VERSION 5.7 ;
BUSBITCHARS "[]" ;
DIVIDERCHAR "/" ;

PROPERTYDEFINITIONS
  MACRO lastSavedExtractCounter INTEGER ;
  MACRO CatenaDesignType STRING ;
  LAYER LEF58_TYPE STRING ;
  LAYER LEF58_SPACING STRING ;
  LAYER LEF58_WIDTH STRING ;
END PROPERTYDEFINITIONS

UNITS
  CAPACITANCE PICOFARADS 1 ;
  DATABASE MICRONS 1000 ;
END UNITS
MANUFACTURINGGRID 0.005 ;
LAYER OVERLAP
  TYPE OVERLAP ;
END OVERLAP

LAYER PW
  TYPE MASTERSLICE ;
  PROPERTY LEF58_TYPE "TYPE PWELL ;" ;
END PW

LAYER NW
  TYPE MASTERSLICE ;
  PROPERTY LEF58_TYPE "TYPE NWELL ;" ;
  PROPERTY LEF58_SPACING "SPACING 0.62 ;" ;
  PROPERTY LEF58_WIDTH "WIDTH 0.62 ;" ;
END NW

LAYER ACT
  TYPE MASTERSLICE ;
  PROPERTY LEF58_TYPE "TYPE DIFFUSION ;" ;
  PROPERTY LEF58_SPACING "SPACING 0.21 ;" ;
  PROPERTY LEF58_WIDTH "WIDTH 0.15 ;" ;
END ACT

LAYER NPLUS
  TYPE IMPLANT ;
  WIDTH 0.31 ;
  SPACING 0.31 ;
  AREA 0.25 ;
END NPLUS

LAYER PPLUS
  TYPE IMPLANT ;
  WIDTH 0.31 ;
  SPACING 0.31 ;
  AREA 0.25 ;
END PPLUS

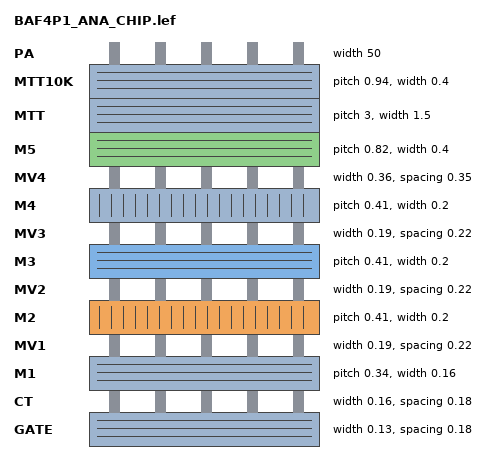
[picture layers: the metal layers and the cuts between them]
LAYER GATE
  TYPE ROUTING ;
  DIRECTION HORIZONTAL ;
  WIDTH 0.13 ;
  AREA 0.09 ;
  SPACING 0.18 ;
  MINENCLOSEDAREA 0.224 ;
  MINIMUMDENSITY 14 ;
  ANTENNAMODEL OXIDE1 ;
    ANTENNAAREARATIO 400 ;
  PROPERTY LEF58_TYPE "TYPE POLYROUTING ;" ;
END GATE

LAYER CT
  TYPE CUT ;
  SPACING 0.18 ;
  SPACING 0.2 ADJACENTCUTS 8 WITHIN 1 ;
  WIDTH 0.16 ;
  ENCLOSURE ABOVE 0 0.05 ;
  ANTENNAMODEL OXIDE1 ;
    ANTENNAAREARATIO 10 ;
END CT

LAYER M1
  TYPE ROUTING ;
  DIRECTION HORIZONTAL ;
  PITCH 0.34 0.34 ;
  WIDTH 0.16 ;
  OFFSET 0.17 0.17 ;
  AREA 0.122 ;
  SPACINGTABLE
    PARALLELRUNLENGTH 0 10.049 
    WIDTH 0 0.18 0.16 
    WIDTH 10.049 0.16 0.6 ;
  MINENCLOSEDAREA 0.2 ;
  MINIMUMDENSITY 15 ;
  MAXIMUMDENSITY 80 ;
  DENSITYCHECKWINDOW 200 200 ;
  DENSITYCHECKSTEP 100 ;
  ANTENNAMODEL OXIDE1 ;
    ANTENNAAREARATIO 600 ;
END M1

LAYER MV1
  TYPE CUT ;
  SPACING 0.22 ;
  SPACING 0.29 ADJACENTCUTS 8 WITHIN 1 ;
  WIDTH 0.19 ;
  ENCLOSURE BELOW 0.01 0.05 ;
  ENCLOSURE ABOVE 0.005 0.05 ;
  ANTENNAMODEL OXIDE1 ;
    ANTENNAAREARATIO 20 ;
END MV1

LAYER M2
  TYPE ROUTING ;
  DIRECTION VERTICAL ;
  PITCH 0.41 0.41 ;
  WIDTH 0.2 ;
  OFFSET 0.205 0.205 ;
  AREA 0.144 ;
  SPACINGTABLE
    PARALLELRUNLENGTH 0 10.049 
    WIDTH 0 0.21 0.2 
    WIDTH 10.049 0.2 0.6 ;
  MINENCLOSEDAREA 0.265 ;
  MINIMUMDENSITY 15 ;
  MAXIMUMDENSITY 80 ;
  DENSITYCHECKWINDOW 200 200 ;
  DENSITYCHECKSTEP 100 ;
  ANTENNAMODEL OXIDE1 ;
    ANTENNAAREARATIO 600 ;
END M2

LAYER MV2
  TYPE CUT ;
  SPACING 0.22 ;
  SPACING 0.29 ADJACENTCUTS 8 WITHIN 1 ;
  WIDTH 0.19 ;
  ENCLOSURE BELOW 0.005 0.05 ;
  ENCLOSURE ABOVE 0.005 0.05 ;
  ANTENNAMODEL OXIDE1 ;
    ANTENNAAREARATIO 20 ;
END MV2

LAYER M3
  TYPE ROUTING ;
  DIRECTION HORIZONTAL ;
  PITCH 0.41 0.41 ;
  WIDTH 0.2 ;
  OFFSET 0.205 0.205 ;
  AREA 0.144 ;
  SPACINGTABLE
    PARALLELRUNLENGTH 0 10.049 
    WIDTH 0 0.21 0.2 
    WIDTH 10.049 0.2 0.6 ;
  MINENCLOSEDAREA 0.265 ;
  MINIMUMDENSITY 15 ;
  MAXIMUMDENSITY 80 ;
  DENSITYCHECKWINDOW 200 200 ;
  DENSITYCHECKSTEP 100 ;
  ANTENNAMODEL OXIDE1 ;
    ANTENNAAREARATIO 600 ;
END M3

LAYER MV3
  TYPE CUT ;
  SPACING 0.22 ;
  SPACING 0.29 ADJACENTCUTS 8 WITHIN 1 ;
  WIDTH 0.19 ;
  ENCLOSURE BELOW 0.005 0.05 ;
  ENCLOSURE ABOVE 0.005 0.05 ;
  ANTENNAMODEL OXIDE1 ;
    ANTENNAAREARATIO 20 ;
END MV3

LAYER M4
  TYPE ROUTING ;
  DIRECTION VERTICAL ;
  PITCH 0.41 0.41 ;
  WIDTH 0.2 ;
  OFFSET 0.205 0.205 ;
  AREA 0.144 ;
  SPACINGTABLE
    PARALLELRUNLENGTH 0 10.049 
    WIDTH 0 0.21 0.2 
    WIDTH 10.049 0.2 0.6 ;
  MINENCLOSEDAREA 0.265 ;
  MINIMUMDENSITY 15 ;
  MAXIMUMDENSITY 80 ;
  DENSITYCHECKWINDOW 200 200 ;
  DENSITYCHECKSTEP 100 ;
  ANTENNAMODEL OXIDE1 ;
    ANTENNAAREARATIO 600 ;
END M4

LAYER MV4
  TYPE CUT ;
  SPACING 0.35 ;
  SPACING 0.54 ADJACENTCUTS 8 WITHIN 1 ;
  WIDTH 0.36 ;
  ENCLOSURE BELOW 0.01 0.05 ;
  ENCLOSURE ABOVE 0.02 0.02 ;
  ANTENNAMODEL OXIDE1 ;
    ANTENNAAREARATIO 20 ;
END MV4

LAYER M5
  TYPE ROUTING ;
  DIRECTION HORIZONTAL ;
  PITCH 0.82 0.82 ;
  WIDTH 0.4 ;
  OFFSET 0.41 0.41 ;
  AREA 0.562 ;
  SPACINGTABLE
    PARALLELRUNLENGTH 0 10.049 
    WIDTH 0 0.42 0.4 
    WIDTH 10.049 0.4 0.6 ;
  MINENCLOSEDAREA 0.565 ;
  MINIMUMDENSITY 20 ;
  MAXIMUMDENSITY 80 ;
  DENSITYCHECKWINDOW 200 200 ;
  DENSITYCHECKSTEP 100 ;
  ANTENNAMODEL OXIDE1 ;
    ANTENNAAREARATIO 600 ;
END M5

LAYER MTT
  TYPE ROUTING ;
  DIRECTION HORIZONTAL ;
  PITCH 3 3 ;
  WIDTH 1.5 ;
  OFFSET 1.5 1.5 ;
  AREA 2.25 ;
  SPACINGTABLE
    PARALLELRUNLENGTH 0 16.049 
    WIDTH 0 1.5 1.5 
    WIDTH 16.049 1.5 3 ;
  MINIMUMDENSITY 30 ;
  DENSITYCHECKWINDOW 200 200 ;
  DENSITYCHECKSTEP 100 ;
  ANTENNAMODEL OXIDE1 ;
    ANTENNAAREARATIO 600 ;
END MTT

LAYER MTT10K
  TYPE ROUTING ;
  DIRECTION HORIZONTAL ;
  PITCH 0.94 0.94 ;
  WIDTH 0.4 ;
  OFFSET 0.47 0.47 ;
  AREA 0.562 ;
  SPACINGTABLE
    PARALLELRUNLENGTH 0 10.049 
    WIDTH 0 0.54 0.4 
    WIDTH 10.049 0.4 0.6 ;
  MINENCLOSEDAREA 0.565 ;
  MINIMUMDENSITY 20 ;
  MAXIMUMDENSITY 80 ;
  DENSITYCHECKWINDOW 200 200 ;
  DENSITYCHECKSTEP 100 ;
  ANTENNAMODEL OXIDE1 ;
    ANTENNAAREARATIO 600 ;
END MTT10K

LAYER PA
  TYPE CUT ;
  PROPERTY LEF58_TYPE "TYPE PASSIVATION ;" ;
  WIDTH 50 ;
  ENCLOSURE BELOW 2 2 ;
END PA

VIARULE PGR GENERATE DEFAULT
  LAYER ACT ;
    ENCLOSURE 0.07 0.07 ;
  LAYER M1 ;
    ENCLOSURE 0.05 0.05 ;
  LAYER CT ;
    RECT -0.08 -0.08 0.08 0.08 ;
    SPACING 0.34 BY 0.34 ;
END PGR

VIARULE REC_PGR GENERATE DEFAULT
  LAYER ACT ;
    ENCLOSURE 0.12 0.12 ;
  LAYER M1 ;
    ENCLOSURE 0.08 0.08 ;
  LAYER CT ;
    RECT -0.08 -0.08 0.08 0.08 ;
    SPACING 0.34 BY 0.34 ;
END REC_PGR

VIARULE NGR GENERATE DEFAULT
  LAYER ACT ;
    ENCLOSURE 0.07 0.07 ;
  LAYER M1 ;
    ENCLOSURE 0.05 0.05 ;
  LAYER CT ;
    RECT -0.08 -0.08 0.08 0.08 ;
    SPACING 0.34 BY 0.34 ;
END NGR

VIARULE REC_NGR GENERATE DEFAULT
  LAYER ACT ;
    ENCLOSURE 0.12 0.12 ;
  LAYER M1 ;
    ENCLOSURE 0.08 0.08 ;
  LAYER CT ;
    RECT -0.08 -0.08 0.08 0.08 ;
    SPACING 0.34 BY 0.34 ;
END REC_NGR

VIARULE M1_ACT GENERATE DEFAULT
  LAYER ACT ;
    ENCLOSURE 0.07 0.07 ;
  LAYER M1 ;
    ENCLOSURE 0.05 0 ;
  LAYER CT ;
    RECT -0.08 -0.08 0.08 0.08 ;
    SPACING 0.34 BY 0.34 ;
END M1_ACT

VIARULE REC_M1_ACT GENERATE DEFAULT
  LAYER ACT ;
    ENCLOSURE 0.12 0.12 ;
  LAYER M1 ;
    ENCLOSURE 0.08 0.08 ;
  LAYER CT ;
    RECT -0.08 -0.08 0.08 0.08 ;
    SPACING 0.34 BY 0.34 ;
END REC_M1_ACT

VIARULE M1_GATE GENERATE DEFAULT
  LAYER GATE ;
    ENCLOSURE 0.07 0.07 ;
  LAYER M1 ;
    ENCLOSURE 0.05 0 ;
  LAYER CT ;
    RECT -0.08 -0.08 0.08 0.08 ;
    SPACING 0.34 BY 0.34 ;
END M1_GATE

VIARULE REC_M1_GATE GENERATE DEFAULT
  LAYER GATE ;
    ENCLOSURE 0.12 0.12 ;
  LAYER M1 ;
    ENCLOSURE 0.08 0.08 ;
  LAYER CT ;
    RECT -0.08 -0.08 0.08 0.08 ;
    SPACING 0.34 BY 0.34 ;
END REC_M1_GATE

VIARULE M2_M1 GENERATE DEFAULT
  LAYER M1 ;
    ENCLOSURE 0.05 0.01 ;
  LAYER M2 ;
    ENCLOSURE 0.05 0.005 ;
  LAYER MV1 ;
    RECT -0.095 -0.095 0.095 0.095 ;
    SPACING 0.41 BY 0.41 ;
END M2_M1

VIARULE REC_M2_M1 GENERATE DEFAULT
  LAYER M1 ;
    ENCLOSURE 0.08 0.05 ;
  LAYER M2 ;
    ENCLOSURE 0.05 0.05 ;
  LAYER MV1 ;
    RECT -0.095 -0.095 0.095 0.095 ;
    SPACING 0.41 BY 0.41 ;
END REC_M2_M1

VIARULE M3_M2 GENERATE DEFAULT
  LAYER M2 ;
    ENCLOSURE 0.05 0.005 ;
  LAYER M3 ;
    ENCLOSURE 0.05 0.005 ;
  LAYER MV2 ;
    RECT -0.095 -0.095 0.095 0.095 ;
    SPACING 0.41 BY 0.41 ;
END M3_M2

VIARULE REC_M3_M2 GENERATE DEFAULT
  LAYER M2 ;
    ENCLOSURE 0.08 0.05 ;
  LAYER M3 ;
    ENCLOSURE 0.05 0.05 ;
  LAYER MV2 ;
    RECT -0.095 -0.095 0.095 0.095 ;
    SPACING 0.41 BY 0.41 ;
END REC_M3_M2

VIARULE M4_M3 GENERATE DEFAULT
  LAYER M3 ;
    ENCLOSURE 0.05 0.005 ;
  LAYER M4 ;
    ENCLOSURE 0.05 0.005 ;
  LAYER MV3 ;
    RECT -0.095 -0.095 0.095 0.095 ;
    SPACING 0.41 BY 0.41 ;
END M4_M3

VIARULE REC_M4_M3 GENERATE DEFAULT
  LAYER M3 ;
    ENCLOSURE 0.08 0.05 ;
  LAYER M4 ;
    ENCLOSURE 0.05 0.05 ;
  LAYER MV3 ;
    RECT -0.095 -0.095 0.095 0.095 ;
    SPACING 0.41 BY 0.41 ;
END REC_M4_M3

VIARULE M5_M4 GENERATE DEFAULT
  LAYER M4 ;
    ENCLOSURE 0.05 0.01 ;
  LAYER M5 ;
    ENCLOSURE 0.11 0.02 ;
  LAYER MV4 ;
    RECT -0.18 -0.18 0.18 0.18 ;
    SPACING 0.71 BY 0.71 ;
END M5_M4

VIARULE M5_M4_SQUARE GENERATE DEFAULT
  LAYER M4 ;
    ENCLOSURE 0.05 0.01 ;
  LAYER M5 ;
    ENCLOSURE 0.09 0.09 ;
  LAYER MV4 ;
    RECT -0.18 -0.18 0.18 0.18 ;
    SPACING 0.71 BY 0.71 ;
END M5_M4_SQUARE

VIARULE MTT_M4 GENERATE DEFAULT
  LAYER M4 ;
    ENCLOSURE 0.05 0.01 ;
  LAYER MTT ;
    ENCLOSURE 0.45 0.3 ;
  LAYER MV4 ;
    RECT -0.18 -0.18 0.18 0.18 ;
    SPACING 0.71 BY 0.71 ;
END MTT_M4

VIARULE MTT10K_M4 GENERATE DEFAULT
  LAYER M4 ;
    ENCLOSURE 0.05 0.01 ;
  LAYER MTT10K ;
    ENCLOSURE 0.11 0.02 ;
  LAYER MV4 ;
    RECT -0.18 -0.18 0.18 0.18 ;
    SPACING 0.71 BY 0.71 ;
END MTT10K_M4

VIARULE MTT10K_M4_SQUARE GENERATE DEFAULT
  LAYER M4 ;
    ENCLOSURE 0.05 0.01 ;
  LAYER MTT10K ;
    ENCLOSURE 0.09 0.09 ;
  LAYER MV4 ;
    RECT -0.18 -0.18 0.18 0.18 ;
    SPACING 0.71 BY 0.71 ;
END MTT10K_M4_SQUARE

VIA M2_M1_0
  VIARULE M2_M1 ;
  CUTSIZE 0.19 0.19 ;
  LAYERS M1 MV1 M2 ;
  CUTSPACING 0.22 0.22 ;
  ENCLOSURE 0.05 0.01 0.05 0.005 ;
  ROWCOL 1 1 ;
END M2_M1_0

VIA M2_M1_1
  VIARULE M2_M1 ;
  CUTSIZE 0.19 0.19 ;
  LAYERS M1 MV1 M2 ;
  CUTSPACING 0.29 0.29 ;
  ENCLOSURE 0.065 0.245 0.065 0.245 ;
  ROWCOL 10 42 ;
END M2_M1_1

VIA M4_M3_2
  VIARULE M4_M3 ;
  CUTSIZE 0.19 0.19 ;
  LAYERS M3 MV3 M4 ;
  CUTSPACING 0.29 0.29 ;
  ENCLOSURE 0.065 0.005 0.065 0.005 ;
  ROWCOL 11 42 ;
END M4_M3_2

VIA M5_M4_3
  VIARULE M5_M4 ;
  CUTSIZE 0.36 0.36 ;
  LAYERS M4 MV4 M5 ;
  CUTSPACING 0.35 0.35 ;
  ENCLOSURE 0.05 0.01 0.11 0.02 ;
  ROWCOL 1 1 ;
END M5_M4_3

VIA M4_M3_4
  VIARULE M4_M3 ;
  CUTSIZE 0.19 0.19 ;
  LAYERS M3 MV3 M4 ;
  CUTSPACING 0.22 0.29 ;
  ENCLOSURE 0.15 0.165 0.15 0.165 ;
  ROWCOL 2 12 ;
END M4_M3_4

VIA M4_M3_5
  VIARULE M4_M3 ;
  CUTSIZE 0.19 0.19 ;
  LAYERS M3 MV3 M4 ;
  CUTSPACING 0.22 0.22 ;
  ENCLOSURE 0.05 0.005 0.05 0.005 ;
  ROWCOL 1 1 ;
END M4_M3_5

VIA M2_M1_6
  VIARULE M2_M1 ;
  CUTSIZE 0.19 0.19 ;
  LAYERS M1 MV1 M2 ;
  CUTSPACING 0.29 0.29 ;
  ENCLOSURE 0.01 0.245 0.005 0.245 ;
  ROWCOL 10 11 ;
END M2_M1_6

VIA M5_M4_7
  VIARULE M5_M4 ;
  CUTSIZE 0.36 0.36 ;
  LAYERS M4 MV4 M5 ;
  CUTSPACING 0.54 0.54 ;
  ENCLOSURE 0.37 0.07 0.37 0.07 ;
  ROWCOL 6 22 ;
END M5_M4_7

VIA M5_M4_8
  VIARULE M5_M4 ;
  CUTSIZE 0.36 0.36 ;
  LAYERS M4 MV4 M5 ;
  CUTSPACING 0.35 0.35 ;
  ENCLOSURE 0.19 0.32 0.19 0.32 ;
  ROWCOL 1 7 ;
END M5_M4_8

VIA M3_M2_9
  VIARULE M3_M2 ;
  CUTSIZE 0.19 0.19 ;
  LAYERS M2 MV2 M3 ;
  CUTSPACING 0.22 0.22 ;
  ENCLOSURE 0.05 0.005 0.05 0.005 ;
  ROWCOL 1 1 ;
END M3_M2_9

VIA M2_M1_10
  VIARULE M2_M1 ;
  CUTSIZE 0.19 0.19 ;
  LAYERS M1 MV1 M2 ;
  CUTSPACING 0.29 0.22 ;
  ENCLOSURE 0.165 0.15 0.165 0.15 ;
  ROWCOL 12 2 ;
END M2_M1_10

VIA M3_M2_11
  VIARULE M3_M2 ;
  CUTSIZE 0.19 0.19 ;
  LAYERS M2 MV2 M3 ;
  CUTSPACING 0.29 0.22 ;
  ENCLOSURE 0.165 0.055 0.165 0.055 ;
  ROWCOL 1 2 ;
END M3_M2_11

VIA M3_M2_12
  VIARULE M3_M2 ;
  CUTSIZE 0.19 0.19 ;
  LAYERS M2 MV2 M3 ;
  CUTSPACING 0.29 0.22 ;
  ENCLOSURE 0.165 0.055 0.165 0.055 ;
  ROWCOL 2 2 ;
END M3_M2_12

VIA M3_M2_13
  VIARULE M3_M2 ;
  CUTSIZE 0.19 0.19 ;
  LAYERS M2 MV2 M3 ;
  CUTSPACING 0.29 0.29 ;
  ENCLOSURE 0.065 0.005 0.065 0.005 ;
  ROWCOL 11 42 ;
END M3_M2_13

VIA M3_M2_14
  VIARULE M3_M2 ;
  CUTSIZE 0.19 0.19 ;
  LAYERS M2 MV2 M3 ;
  CUTSPACING 0.29 0.22 ;
  ENCLOSURE 0.165 0.055 0.165 0.055 ;
  ROWCOL 12 2 ;
END M3_M2_14

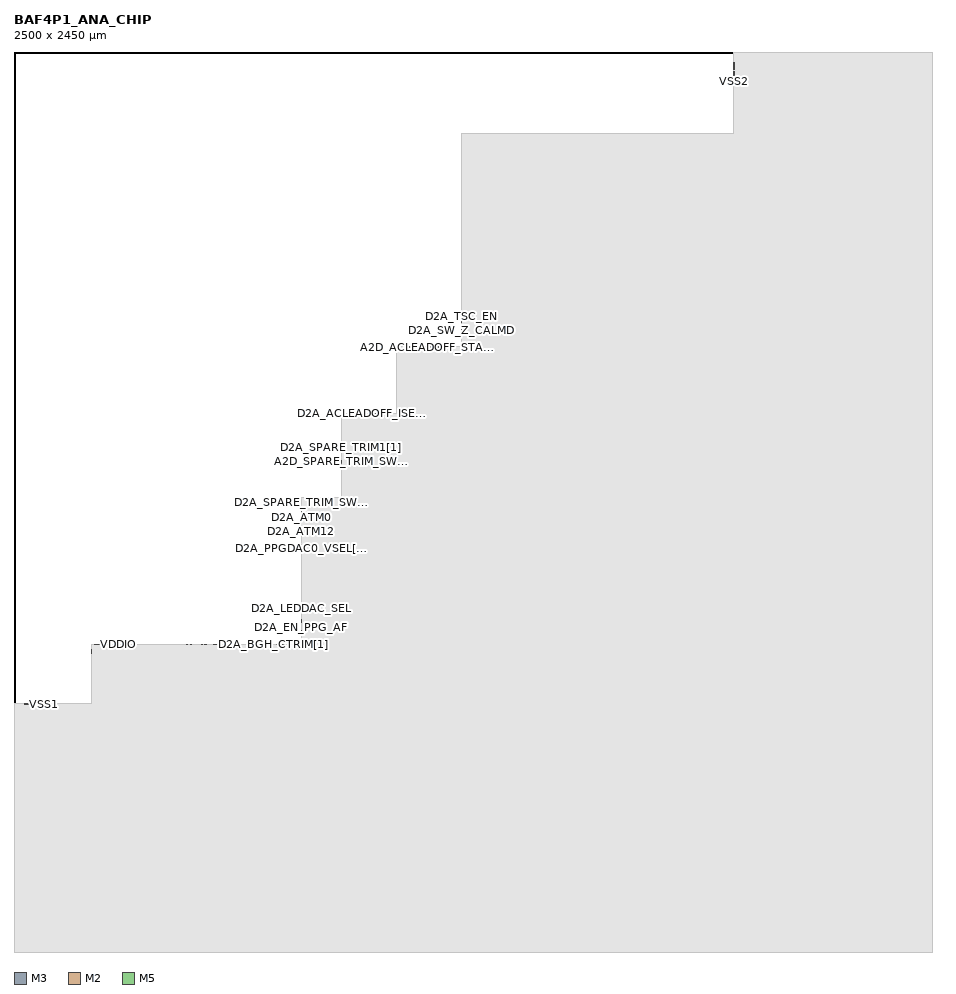
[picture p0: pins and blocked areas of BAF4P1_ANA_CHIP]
MACRO BAF4P1_ANA_CHIP
  CLASS BLOCK ;
  ORIGIN 0 0 ;
  FOREIGN BAF4P1_ANA_CHIP 0 0 ;
  SIZE 2500 BY 2450 ;
  PIN D2A_ECG_DDA_ISEL[0]
    DIRECTION INPUT ;
    USE SIGNAL ;
    PORT
      LAYER M3 ;
        RECT 1154.455 1646.7 1154.755 1647 ;
    END
  END D2A_ECG_DDA_ISEL[0]
  PIN D2A_ECG_DDA_GSEL[1]
    DIRECTION INPUT ;
    USE SIGNAL ;
    PORT
      LAYER M3 ;
        RECT 1145.355 1646.7 1145.655 1647 ;
    END
  END D2A_ECG_DDA_GSEL[1]
  PIN D2A_EN_PPG_BUFFER
    DIRECTION INPUT ;
    USE SIGNAL ;
    PORT
      LAYER M3 ;
        RECT 782 878.81 782.2 879.11 ;
    END
  END D2A_EN_PPG_BUFFER
  PIN D2A_LED_EN
    DIRECTION INPUT ;
    USE SIGNAL ;
    PORT
      LAYER M3 ;
        RECT 782 908.71 782.2 909.01 ;
    END
  END D2A_LED_EN
  PIN D2A_PPG_TEST_IN[0]
    DIRECTION INPUT ;
    USE SIGNAL ;
    PORT
      LAYER M3 ;
        RECT 782 885.31 782.2 885.61 ;
    END
  END D2A_PPG_TEST_IN[0]
  PIN A2D_SPARE_TRIM_SW0[1]
    DIRECTION OUTPUT ;
    USE SIGNAL ;
    PORT
      LAYER M3 ;
        RECT 891.37 1336.39 891.67 1337.39 ;
    END
  END A2D_SPARE_TRIM_SW0[1]
  PIN D2A_EN_PPG_AF
    DIRECTION INPUT ;
    USE SIGNAL ;
    PORT
      LAYER M3 ;
        RECT 782 882.71 782.2 883.01 ;
    END
  END D2A_EN_PPG_AF
  PIN D2A_LED_STANDBYEN
    DIRECTION INPUT ;
    USE SIGNAL ;
    PORT
      LAYER M3 ;
        RECT 782 907.41 782.2 907.71 ;
    END
  END D2A_LED_STANDBYEN
  PIN D2A_SPARE_TRIM_SW0[1]
    DIRECTION INPUT ;
    USE SIGNAL ;
    PORT
      LAYER M3 ;
        RECT 782 1193.84 782.3 1194.14 ;
    END
  END D2A_SPARE_TRIM_SW0[1]
  PIN D2A_TSC_INA_EN
    DIRECTION INPUT ;
    USE SIGNAL ;
    PORT
      LAYER M3 ;
        RECT 1217.84 1719.36 1218.14 1719.66 ;
    END
  END D2A_TSC_INA_EN
  PIN VSS_DIG_AO
    DIRECTION INOUT ;
    USE SIGNAL ;
    PORT
      LAYER M2 ;
        RECT 721.265 835.925 722.265 836.225 ;
    END
    PORT
      LAYER M2 ;
        RECT 691.245 835.925 692.245 836.225 ;
    END
    PORT
      LAYER M2 ;
        RECT 556.465 835.925 557.465 836.225 ;
    END
    PORT
      LAYER M2 ;
        RECT 468.87 835.925 469.87 836.225 ;
    END
    PORT
      LAYER M3 ;
        RECT 509.465 835.925 514.465 836.225 ;
    END
    PORT
      LAYER M2 ;
        RECT 782 1157.215 782.3 1158.215 ;
    END
    PORT
      LAYER M2 ;
        RECT 782 871.21 782.2 872.21 ;
    END
    PORT
      LAYER M2 ;
        RECT 782 920.31 782.3 921.31 ;
    END
    PORT
      LAYER M2 ;
        RECT 782 1189.54 782.3 1190.54 ;
    END
    PORT
      LAYER M2 ;
        RECT 1217.84 1667.005 1218.14 1668.005 ;
    END
    PORT
      LAYER M2 ;
        RECT 891.37 1328.895 891.67 1329.895 ;
    END
    PORT
      LAYER M2 ;
        RECT 891.37 1356.66 891.67 1357.66 ;
    END
    PORT
      LAYER M2 ;
        RECT 891.37 1382.375 891.67 1383.375 ;
    END
    PORT
      LAYER M2 ;
        RECT 1164.555 1646.7 1165.555 1647 ;
    END
    PORT
      LAYER M2 ;
        RECT 782 1099.485 782.2 1100.485 ;
    END
    PORT
      LAYER M2 ;
        RECT 1217.84 1714.655 1218.14 1715.655 ;
    END
    PORT
      LAYER M2 ;
        RECT 981.735 1464.88 982.735 1465.18 ;
    END
    PORT
      LAYER M2 ;
        RECT 923.735 1464.88 924.735 1465.18 ;
    END
    PORT
      LAYER M2 ;
        RECT 782 1138.835 782.3 1139.835 ;
    END
    PORT
      LAYER M2 ;
        RECT 1068.26 1646.7 1069.26 1647 ;
    END
  END VSS_DIG_AO
  PIN D2A_ACLEADOFF_VTHPSEL_TRIM[2]
    DIRECTION INPUT ;
    USE SIGNAL ;
    PORT
      LAYER M3 ;
        RECT 1112.755 1646.7 1113.055 1647 ;
    END
  END D2A_ACLEADOFF_VTHPSEL_TRIM[2]
  PIN D2A_DCLEADOFF_ISEL_TRIM[6]
    DIRECTION INPUT ;
    USE SIGNAL ;
    PORT
      LAYER M3 ;
        RECT 957.335 1464.88 957.635 1465.18 ;
    END
  END D2A_DCLEADOFF_ISEL_TRIM[6]
  PIN D2A_DCLEADOFF_ISEL_TRIM[7]
    DIRECTION INPUT ;
    USE SIGNAL ;
    PORT
      LAYER M3 ;
        RECT 956.035 1464.88 956.335 1465.18 ;
    END
  END D2A_DCLEADOFF_ISEL_TRIM[7]
  PIN D2A_TIA_GAIN[0]
    DIRECTION INPUT ;
    USE SIGNAL ;
    PORT
      LAYER M3 ;
        RECT 782 906.11 782.2 906.41 ;
    END
  END D2A_TIA_GAIN[0]
  PIN A2D_external_clock_I
    DIRECTION OUTPUT ;
    USE SIGNAL ;
    PORT
      LAYER M3 ;
        RECT 522.465 835.925 523.465 836.225 ;
    END
  END A2D_external_clock_I
  PIN D2A_EN_PPGDAC_BUFFER
    DIRECTION INPUT ;
    USE SIGNAL ;
    PORT
      LAYER M3 ;
        RECT 782 913.91 782.2 914.21 ;
    END
  END D2A_EN_PPGDAC_BUFFER
  PIN D2A_ECG_PGA_GSEL[1]
    DIRECTION INPUT ;
    USE SIGNAL ;
    PORT
      LAYER M3 ;
        RECT 1160.955 1646.7 1161.255 1647 ;
    END
  END D2A_ECG_PGA_GSEL[1]
  PIN D2A_ACLEADOFF_VTHPSEL_TRIM[1]
    DIRECTION INPUT ;
    USE SIGNAL ;
    PORT
      LAYER M3 ;
        RECT 1111.455 1646.7 1111.755 1647 ;
    END
  END D2A_ACLEADOFF_VTHPSEL_TRIM[1]
  PIN D2A_DCLEADOFF_COMP_TH_TRIM[7]
    DIRECTION INPUT ;
    USE SIGNAL ;
    PORT
      LAYER M3 ;
        RECT 949.535 1464.88 949.835 1465.18 ;
    END
  END D2A_DCLEADOFF_COMP_TH_TRIM[7]
  PIN D2A_ECGCAL_EN
    DIRECTION INPUT ;
    USE SIGNAL ;
    PORT
      LAYER M3 ;
        RECT 1141.755 1646.7 1142.055 1647 ;
    END
  END D2A_ECGCAL_EN
  PIN D2A_TIA_IDAC[6]
    DIRECTION INPUT ;
    USE SIGNAL ;
    PORT
      LAYER M3 ;
        RECT 782 887.91 782.2 888.21 ;
    END
  END D2A_TIA_IDAC[6]
  PIN D2A_DCLEADOFF_COMP_TH_TRIM[6]
    DIRECTION INPUT ;
    USE SIGNAL ;
    PORT
      LAYER M3 ;
        RECT 950.835 1464.88 951.135 1465.18 ;
    END
  END D2A_DCLEADOFF_COMP_TH_TRIM[6]
  PIN D2A_DCLEADOFF_COMP_TH_TRIM[3]
    DIRECTION INPUT ;
    USE SIGNAL ;
    PORT
      LAYER M3 ;
        RECT 954.735 1464.88 955.035 1465.18 ;
    END
  END D2A_DCLEADOFF_COMP_TH_TRIM[3]
  PIN D2A_PPGDAC0_VSEL[1]
    DIRECTION INPUT ;
    USE SIGNAL ;
    PORT
      LAYER M3 ;
        RECT 782 1120.685 782.3 1120.985 ;
    END
  END D2A_PPGDAC0_VSEL[1]
  PIN D2A_SPARE_TRIM0[6]
    DIRECTION INPUT ;
    USE SIGNAL ;
    PORT
      LAYER M3 ;
        RECT 978.135 1464.88 978.435 1465.18 ;
    END
  END D2A_SPARE_TRIM0[6]
  PIN D2A_SW_Z_DDS[3]
    DIRECTION INPUT ;
    USE SIGNAL ;
    PORT
      LAYER M3 ;
        RECT 1217.84 1685.68 1218.14 1685.98 ;
    END
  END D2A_SW_Z_DDS[3]
  PIN D2A_PPGDAC1_VSEL[9]
    DIRECTION INPUT ;
    USE SIGNAL ;
    PORT
      LAYER M3 ;
        RECT 782 1114.185 782.3 1114.485 ;
    END
  END D2A_PPGDAC1_VSEL[9]
  PIN D2A_DCLEADOFF_COMP_TH_TRIM[4]
    DIRECTION INPUT ;
    USE SIGNAL ;
    PORT
      LAYER M3 ;
        RECT 953.435 1464.88 953.735 1465.18 ;
    END
  END D2A_DCLEADOFF_COMP_TH_TRIM[4]
  PIN D2A_ATM3
    DIRECTION INPUT ;
    USE SIGNAL ;
    PORT
      LAYER M3 ;
        RECT 782 1178.74 782.3 1179.04 ;
    END
  END D2A_ATM3
  PIN D2A_ECGCAL_VSEL_TRIM[2]
    DIRECTION INPUT ;
    USE SIGNAL ;
    PORT
      LAYER M3 ;
        RECT 1131.355 1646.7 1131.655 1647 ;
    END
  END D2A_ECGCAL_VSEL_TRIM[2]
  PIN D2A_ACLEADOFF_ISEL_TRIM[1]
    DIRECTION INPUT ;
    USE SIGNAL ;
    PORT
      LAYER M3 ;
        RECT 1119.255 1646.7 1119.555 1647 ;
    END
  END D2A_ACLEADOFF_ISEL_TRIM[1]
  PIN D2A_TSC_EN
    DIRECTION INPUT ;
    USE SIGNAL ;
    PORT
      LAYER M3 ;
        RECT 1217.84 1708.405 1218.14 1708.705 ;
    END
  END D2A_TSC_EN
  PIN D2A_SPARE_TRIM2[1]
    DIRECTION INPUT ;
    USE SIGNAL ;
    PORT
      LAYER M3 ;
        RECT 891.37 1361.885 891.67 1362.185 ;
    END
  END D2A_SPARE_TRIM2[1]
  PIN D2A_OSC_ISEL_TRIM[1]
    DIRECTION INPUT ;
    USE SIGNAL ;
    PORT
      LAYER M3 ;
        RECT 734.765 835.925 735.065 836.225 ;
    END
  END D2A_OSC_ISEL_TRIM[1]
  PIN D2A_SPARE_TRIM2[6]
    DIRECTION INPUT ;
    USE SIGNAL ;
    PORT
      LAYER M3 ;
        RECT 891.37 1368.385 891.67 1368.685 ;
    END
  END D2A_SPARE_TRIM2[6]
  PIN D2A_LDO1V5_VTRIM[4]
    DIRECTION INPUT ;
    USE SIGNAL ;
    PORT
      LAYER M3 ;
        RECT 479.17 835.925 479.47 836.225 ;
    END
  END D2A_LDO1V5_VTRIM[4]
  PIN D2A_ACLEADOFF_ISEL_TRIM[7]
    DIRECTION INPUT ;
    USE SIGNAL ;
    PORT
      LAYER M3 ;
        RECT 941.735 1464.88 942.035 1465.18 ;
    END
  END D2A_ACLEADOFF_ISEL_TRIM[7]
  PIN A2D_SPARE_TRIM_SW0[2]
    DIRECTION OUTPUT ;
    USE SIGNAL ;
    PORT
      LAYER M3 ;
        RECT 891.37 1339.39 891.67 1340.39 ;
    END
  END A2D_SPARE_TRIM_SW0[2]
  PIN D2A_SDM_BIAS[0]
    DIRECTION INPUT ;
    USE SIGNAL ;
    PORT
      LAYER M3 ;
        RECT 1077.855 1646.7 1078.155 1647 ;
    END
  END D2A_SDM_BIAS[0]
  PIN D2A_BIST_EN
    DIRECTION INPUT ;
    USE SIGNAL ;
    PORT
      LAYER M3 ;
        RECT 782 1160.54 782.3 1160.84 ;
    END
  END D2A_BIST_EN
  PIN D2A_PPGDAC0_VSEL[6]
    DIRECTION INPUT ;
    USE SIGNAL ;
    PORT
      LAYER M3 ;
        RECT 782 1127.185 782.3 1127.485 ;
    END
  END D2A_PPGDAC0_VSEL[6]
  PIN D2A_BGH_CTRIM[0]
    DIRECTION INPUT ;
    USE SIGNAL ;
    PORT
      LAYER M3 ;
        RECT 705.915 835.925 706.215 836.225 ;
    END
  END D2A_BGH_CTRIM[0]
  PIN D2A_BIST_ISEL[1]
    DIRECTION INPUT ;
    USE SIGNAL ;
    PORT
      LAYER M3 ;
        RECT 782 1163.14 782.3 1163.44 ;
    END
  END D2A_BIST_ISEL[1]
  PIN D2A_VCM1P5_BUF_EN
    DIRECTION INPUT ;
    USE SIGNAL ;
    PORT
      LAYER M3 ;
        RECT 782 1183.94 782.3 1184.24 ;
    END
  END D2A_VCM1P5_BUF_EN
  PIN D2A_SPARE_TRIM1[7]
    DIRECTION INPUT ;
    USE SIGNAL ;
    PORT
      LAYER M3 ;
        RECT 891.37 1380.085 891.67 1380.385 ;
    END
  END D2A_SPARE_TRIM1[7]
  PIN D2A_ATM6
    DIRECTION INPUT ;
    USE SIGNAL ;
    PORT
      LAYER M3 ;
        RECT 782 1174.84 782.3 1175.14 ;
    END
  END D2A_ATM6
  PIN D2A_EN_TIA
    DIRECTION INPUT ;
    USE SIGNAL ;
    PORT
      LAYER M3 ;
        RECT 782 900.91 782.2 901.21 ;
    END
  END D2A_EN_TIA
  PIN D2A_Z_EN
    DIRECTION INPUT ;
    USE SIGNAL ;
    PORT
      LAYER M3 ;
        RECT 1217.84 1692.18 1218.14 1692.48 ;
    END
  END D2A_Z_EN
  PIN D2A_PPGDAC0_VSEL[5]
    DIRECTION INPUT ;
    USE SIGNAL ;
    PORT
      LAYER M3 ;
        RECT 782 1125.885 782.3 1126.185 ;
    END
  END D2A_PPGDAC0_VSEL[5]
  PIN D2A_SW_Z_TX_GSEL[0]
    DIRECTION INPUT ;
    USE SIGNAL ;
    PORT
      LAYER M3 ;
        RECT 1217.84 1675.305 1218.14 1675.605 ;
    END
  END D2A_SW_Z_TX_GSEL[0]
  PIN D2A_TIA_IDAC[7]
    DIRECTION INPUT ;
    USE SIGNAL ;
    PORT
      LAYER M3 ;
        RECT 782 886.61 782.2 886.91 ;
    END
  END D2A_TIA_IDAC[7]
  PIN D2A_PPG_TEST_OUT[0]
    DIRECTION INPUT ;
    USE SIGNAL ;
    PORT
      LAYER M3 ;
        RECT 782 876.21 782.2 876.51 ;
    END
  END D2A_PPG_TEST_OUT[0]
  PIN D2A_DCLEADOFF_RMODE_EN
    DIRECTION INPUT ;
    USE SIGNAL ;
    PORT
      LAYER M3 ;
        RECT 1095.15 1646.7 1095.45 1647 ;
    END
  END D2A_DCLEADOFF_RMODE_EN
  PIN D2A_TSC_OUT_SEL
    DIRECTION INPUT ;
    USE SIGNAL ;
    PORT
      LAYER M3 ;
        RECT 1217.84 1707.105 1218.14 1707.405 ;
    END
  END D2A_TSC_OUT_SEL
  PIN D2A_SPARE_TRIM0[5]
    DIRECTION INPUT ;
    USE SIGNAL ;
    PORT
      LAYER M3 ;
        RECT 976.835 1464.88 977.135 1465.18 ;
    END
  END D2A_SPARE_TRIM0[5]
  PIN D2A_SPARE_TRIM_SW1[2]
    DIRECTION INPUT ;
    USE SIGNAL ;
    PORT
      LAYER M3 ;
        RECT 686.345 835.925 686.645 836.225 ;
    END
  END D2A_SPARE_TRIM_SW1[2]
  PIN D2A_SPARE_TRIM_SW1[5]
    DIRECTION INPUT ;
    USE SIGNAL ;
    PORT
      LAYER M3 ;
        RECT 682.445 835.925 682.745 836.225 ;
    END
  END D2A_SPARE_TRIM_SW1[5]
  PIN D2A_SPARE_TRIM0[0]
    DIRECTION INPUT ;
    USE SIGNAL ;
    PORT
      LAYER M3 ;
        RECT 970.335 1464.88 970.635 1465.18 ;
    END
  END D2A_SPARE_TRIM0[0]
  PIN D2A_SPARE_TRIM_SW1[3]
    DIRECTION INPUT ;
    USE SIGNAL ;
    PORT
      LAYER M3 ;
        RECT 685.045 835.925 685.345 836.225 ;
    END
  END D2A_SPARE_TRIM_SW1[3]
  PIN D2A_SPARE_TRIM0[7]
    DIRECTION INPUT ;
    USE SIGNAL ;
    PORT
      LAYER M3 ;
        RECT 979.435 1464.88 979.735 1465.18 ;
    END
  END D2A_SPARE_TRIM0[7]
  PIN D2A_RLD_EN
    DIRECTION INPUT ;
    USE SIGNAL ;
    PORT
      LAYER M3 ;
        RECT 1086.655 1646.7 1086.955 1647 ;
    END
  END D2A_RLD_EN
  PIN D2A_SPARE_TRIM0[3]
    DIRECTION INPUT ;
    USE SIGNAL ;
    PORT
      LAYER M3 ;
        RECT 974.235 1464.88 974.535 1465.18 ;
    END
  END D2A_SPARE_TRIM0[3]
  PIN D2A_TIA_IDAC[2]
    DIRECTION INPUT ;
    USE SIGNAL ;
    PORT
      LAYER M3 ;
        RECT 782 893.11 782.2 893.41 ;
    END
  END D2A_TIA_IDAC[2]
  PIN D2A_SPARE_TRIM1[4]
    DIRECTION INPUT ;
    USE SIGNAL ;
    PORT
      LAYER M3 ;
        RECT 891.37 1376.185 891.67 1376.485 ;
    END
  END D2A_SPARE_TRIM1[4]
  PIN D2A_ECG_PGA_EN
    DIRECTION INPUT ;
    USE SIGNAL ;
    PORT
      LAYER M3 ;
        RECT 1157.055 1646.7 1157.355 1647 ;
    END
  END D2A_ECG_PGA_EN
  PIN VSS1
    DIRECTION INOUT ;
    USE SIGNAL ;
    PORT
      LAYER M3 ;
        RECT 79.66 673.5 83.66 675.5 ;
    END
  END VSS1
  PIN A2D_SPARE_TRIM_SW0[5]
    DIRECTION OUTPUT ;
    USE SIGNAL ;
    PORT
      LAYER M3 ;
        RECT 891.37 1348.39 891.67 1349.39 ;
    END
  END A2D_SPARE_TRIM_SW0[5]
  PIN D2A_TIA_IDAC[0]
    DIRECTION INPUT ;
    USE SIGNAL ;
    PORT
      LAYER M3 ;
        RECT 782 895.71 782.2 896.01 ;
    END
  END D2A_TIA_IDAC[0]
  PIN D2A_ECG_DDA_ISEL[1]
    DIRECTION INPUT ;
    USE SIGNAL ;
    PORT
      LAYER M3 ;
        RECT 1155.755 1646.7 1156.055 1647 ;
    END
  END D2A_ECG_DDA_ISEL[1]
  PIN D2A_ACLEADOFF_VTHNSEL_TRIM[1]
    DIRECTION INPUT ;
    USE SIGNAL ;
    PORT
      LAYER M3 ;
        RECT 1115.355 1646.7 1115.655 1647 ;
    END
  END D2A_ACLEADOFF_VTHNSEL_TRIM[1]
  PIN D2A_SPARE_TRIM3[4]
    DIRECTION INPUT ;
    USE SIGNAL ;
    PORT
      LAYER M3 ;
        RECT 782 930.51 782.3 930.81 ;
    END
  END D2A_SPARE_TRIM3[4]
  PIN D2A_SPARE_TRIM3[6]
    DIRECTION INPUT ;
    USE SIGNAL ;
    PORT
      LAYER M3 ;
        RECT 782 933.11 782.3 933.41 ;
    END
  END D2A_SPARE_TRIM3[6]
  PIN D2A_SPARE_TRIM2[2]
    DIRECTION INPUT ;
    USE SIGNAL ;
    PORT
      LAYER M3 ;
        RECT 891.37 1363.185 891.67 1363.485 ;
    END
  END D2A_SPARE_TRIM2[2]
  PIN D2A_ATM11
    DIRECTION INPUT ;
    USE SIGNAL ;
    PORT
      LAYER M3 ;
        RECT 782 1167.04 782.3 1167.34 ;
    END
  END D2A_ATM11
  PIN D2A_BIST_ISEL[2]
    DIRECTION INPUT ;
    USE SIGNAL ;
    PORT
      LAYER M3 ;
        RECT 782 1164.44 782.3 1164.74 ;
    END
  END D2A_BIST_ISEL[2]
  PIN D2A_OSC_TRIM[6]
    DIRECTION INPUT ;
    USE SIGNAL ;
    PORT
      LAYER M3 ;
        RECT 696.835 835.925 697.135 836.225 ;
    END
  END D2A_OSC_TRIM[6]
  PIN D2A_DCLEADOFF_ISEL_TRIM[5]
    DIRECTION INPUT ;
    USE SIGNAL ;
    PORT
      LAYER M3 ;
        RECT 958.635 1464.88 958.935 1465.18 ;
    END
  END D2A_DCLEADOFF_ISEL_TRIM[5]
  PIN D2A_ATM10
    DIRECTION INPUT ;
    USE SIGNAL ;
    PORT
      LAYER M3 ;
        RECT 782 1168.34 782.3 1168.64 ;
    END
  END D2A_ATM10
  PIN D2A_DCLEADOFF_COMP_TH_TRIM[5]
    DIRECTION INPUT ;
    USE SIGNAL ;
    PORT
      LAYER M3 ;
        RECT 952.135 1464.88 952.435 1465.18 ;
    END
  END D2A_DCLEADOFF_COMP_TH_TRIM[5]
  PIN D2A_ATM1
    DIRECTION INPUT ;
    USE SIGNAL ;
    PORT
      LAYER M3 ;
        RECT 782 1181.34 782.3 1181.64 ;
    END
  END D2A_ATM1
  PIN D2A_ECG_DDA_CLKSEL[1]
    DIRECTION INPUT ;
    USE SIGNAL ;
    PORT
      LAYER M3 ;
        RECT 1150.555 1646.7 1150.855 1647 ;
    END
  END D2A_ECG_DDA_CLKSEL[1]
  PIN D2A_ECGCAL_VSEL_TRIM[5]
    DIRECTION INPUT ;
    USE SIGNAL ;
    PORT
      LAYER M3 ;
        RECT 1135.255 1646.7 1135.555 1647 ;
    END
  END D2A_ECGCAL_VSEL_TRIM[5]
  PIN D2A_SPARE_TRIM0[4]
    DIRECTION INPUT ;
    USE SIGNAL ;
    PORT
      LAYER M3 ;
        RECT 975.535 1464.88 975.835 1465.18 ;
    END
  END D2A_SPARE_TRIM0[4]
  PIN D2A_SW_Z_RXGAIN
    DIRECTION INPUT ;
    USE SIGNAL ;
    PORT
      LAYER M3 ;
        RECT 1217.84 1693.48 1218.14 1693.78 ;
    END
  END D2A_SW_Z_RXGAIN
  PIN D2A_DCLEADOFF_VINFLIP
    DIRECTION INPUT ;
    USE SIGNAL ;
    PORT
      LAYER M3 ;
        RECT 1093.85 1646.7 1094.15 1647 ;
    END
  END D2A_DCLEADOFF_VINFLIP
  PIN D2A_ACLEADOFF_EN
    DIRECTION INPUT ;
    USE SIGNAL ;
    PORT
      LAYER M3 ;
        RECT 1120.555 1646.7 1120.855 1647 ;
    END
  END D2A_ACLEADOFF_EN
  PIN D2A_SPARE_TRIM_SW1[1]
    DIRECTION INPUT ;
    USE SIGNAL ;
    PORT
      LAYER M3 ;
        RECT 687.645 835.925 687.945 836.225 ;
    END
  END D2A_SPARE_TRIM_SW1[1]
  PIN D2A_PPGDAC1_VSEL[3]
    DIRECTION INPUT ;
    USE SIGNAL ;
    PORT
      LAYER M3 ;
        RECT 782 1106.385 782.3 1106.685 ;
    END
  END D2A_PPGDAC1_VSEL[3]
  PIN D2A_PPGDAC1_VSEL[11]
    DIRECTION INPUT ;
    USE SIGNAL ;
    PORT
      LAYER M3 ;
        RECT 782 1116.785 782.3 1117.085 ;
    END
  END D2A_PPGDAC1_VSEL[11]
  PIN D2A_TIA_IDAC[3]
    DIRECTION INPUT ;
    USE SIGNAL ;
    PORT
      LAYER M3 ;
        RECT 782 891.81 782.2 892.11 ;
    END
  END D2A_TIA_IDAC[3]
  PIN D2A_TIA_IDAC[1]
    DIRECTION INPUT ;
    USE SIGNAL ;
    PORT
      LAYER M3 ;
        RECT 782 894.41 782.2 894.71 ;
    END
  END D2A_TIA_IDAC[1]
  PIN A2D_external_RESET
    DIRECTION OUTPUT ;
    USE SIGNAL ;
    PORT
      LAYER M3 ;
        RECT 528.465 835.92 529.465 836.22 ;
    END
  END A2D_external_RESET
  PIN D2A_ECG_LPF_EN
    DIRECTION INPUT ;
    USE SIGNAL ;
    PORT
      LAYER M3 ;
        RECT 1158.355 1646.7 1158.655 1647 ;
    END
  END D2A_ECG_LPF_EN
  PIN D2A_BGH_VTRIM[7]
    DIRECTION INPUT ;
    USE SIGNAL ;
    PORT
      LAYER M3 ;
        RECT 484.255 835.915 484.555 836.215 ;
    END
  END D2A_BGH_VTRIM[7]
  PIN D2A_BGH_VTRIM[5]
    DIRECTION INPUT ;
    USE SIGNAL ;
    PORT
      LAYER M3 ;
        RECT 486.855 835.925 487.155 836.225 ;
    END
  END D2A_BGH_VTRIM[5]
  PIN D2A_ACLEADOFF_ISEL_TRIM[3]
    DIRECTION INPUT ;
    USE SIGNAL ;
    PORT
      LAYER M3 ;
        RECT 946.935 1464.88 947.235 1465.18 ;
    END
  END D2A_ACLEADOFF_ISEL_TRIM[3]
  PIN D2A_BGH_VTRIM[4]
    DIRECTION INPUT ;
    USE SIGNAL ;
    PORT
      LAYER M3 ;
        RECT 488.155 835.925 488.455 836.225 ;
    END
  END D2A_BGH_VTRIM[4]
  PIN A2D_SW_POWER_POR
    DIRECTION OUTPUT ;
    USE SIGNAL ;
    PORT
      LAYER M3 ;
        RECT 543.47 835.925 544.47 836.225 ;
    END
  END A2D_SW_POWER_POR
  PIN D2A_BGH_VTRIM[0]
    DIRECTION INPUT ;
    USE SIGNAL ;
    PORT
      LAYER M3 ;
        RECT 493.355 835.925 493.655 836.225 ;
    END
  END D2A_BGH_VTRIM[0]
  PIN D2A_BGH_VTRIM[1]
    DIRECTION INPUT ;
    USE SIGNAL ;
    PORT
      LAYER M3 ;
        RECT 492.055 835.925 492.355 836.225 ;
    END
  END D2A_BGH_VTRIM[1]
  PIN D2A_BGH_VTRIM[3]
    DIRECTION INPUT ;
    USE SIGNAL ;
    PORT
      LAYER M3 ;
        RECT 489.455 835.925 489.755 836.225 ;
    END
  END D2A_BGH_VTRIM[3]
  PIN DVDD1P5_ANA
    DIRECTION INOUT ;
    USE SIGNAL ;
    PORT
      LAYER M3 ;
        RECT 212 812.83 212.2 822.83 ;
    END
  END DVDD1P5_ANA
  PIN D2A_LDO1V5_VTRIM[0]
    DIRECTION INPUT ;
    USE SIGNAL ;
    PORT
      LAYER M3 ;
        RECT 473.97 835.925 474.27 836.225 ;
    END
  END D2A_LDO1V5_VTRIM[0]
  PIN D2A_LDO1V5_VTRIM[1]
    DIRECTION INPUT ;
    USE SIGNAL ;
    PORT
      LAYER M3 ;
        RECT 475.27 835.925 475.57 836.225 ;
    END
  END D2A_LDO1V5_VTRIM[1]
  PIN D2A_OSC_TRIM[7]
    DIRECTION INPUT ;
    USE SIGNAL ;
    PORT
      LAYER M3 ;
        RECT 695.535 835.925 695.835 836.225 ;
    END
  END D2A_OSC_TRIM[7]
  PIN D2A_PPGDAC0_VSEL[9]
    DIRECTION INPUT ;
    USE SIGNAL ;
    PORT
      LAYER M3 ;
        RECT 782 1131.085 782.3 1131.385 ;
    END
  END D2A_PPGDAC0_VSEL[9]
  PIN VREF0P8
    DIRECTION INOUT ;
    USE SIGNAL ;
    PORT
      LAYER M3 ;
        RECT 270 835.925 275 836.225 ;
    END
  END VREF0P8
  PIN D2A_SW_Z_DDS[9]
    DIRECTION INPUT ;
    USE SIGNAL ;
    PORT
      LAYER M3 ;
        RECT 1217.84 1677.88 1218.14 1678.18 ;
    END
  END D2A_SW_Z_DDS[9]
  PIN D2A_SW_Z_DDS[8]
    DIRECTION INPUT ;
    USE SIGNAL ;
    PORT
      LAYER M3 ;
        RECT 1217.84 1679.18 1218.14 1679.48 ;
    END
  END D2A_SW_Z_DDS[8]
  PIN D2A_SW_Z_DDS[7]
    DIRECTION INPUT ;
    USE SIGNAL ;
    PORT
      LAYER M3 ;
        RECT 1217.84 1680.48 1218.14 1680.78 ;
    END
  END D2A_SW_Z_DDS[7]
  PIN D2A_SW_Z_DDS[6]
    DIRECTION INPUT ;
    USE SIGNAL ;
    PORT
      LAYER M3 ;
        RECT 1217.84 1681.78 1218.14 1682.08 ;
    END
  END D2A_SW_Z_DDS[6]
  PIN D2A_SW_Z_DDS[5]
    DIRECTION INPUT ;
    USE SIGNAL ;
    PORT
      LAYER M3 ;
        RECT 1217.84 1683.08 1218.14 1683.38 ;
    END
  END D2A_SW_Z_DDS[5]
  PIN D2A_SW_Z_DDS[4]
    DIRECTION INPUT ;
    USE SIGNAL ;
    PORT
      LAYER M3 ;
        RECT 1217.84 1684.38 1218.14 1684.68 ;
    END
  END D2A_SW_Z_DDS[4]
  PIN D2A_SPARE_TRIM2[3]
    DIRECTION INPUT ;
    USE SIGNAL ;
    PORT
      LAYER M3 ;
        RECT 891.37 1364.485 891.67 1364.785 ;
    END
  END D2A_SPARE_TRIM2[3]
  PIN D2A_ECG_PGA_GSEL[0]
    DIRECTION INPUT ;
    USE SIGNAL ;
    PORT
      LAYER M3 ;
        RECT 1159.655 1646.7 1159.955 1647 ;
    END
  END D2A_ECG_PGA_GSEL[0]
  PIN D2A_ECG_DDA_EN
    DIRECTION INPUT ;
    USE SIGNAL ;
    PORT
      LAYER M3 ;
        RECT 1146.655 1646.7 1146.955 1647 ;
    END
  END D2A_ECG_DDA_EN
  PIN VDD_DIG_ZMEASURE
    DIRECTION INOUT ;
    USE SIGNAL ;
    PORT
      LAYER M3 ;
        RECT 1217.84 1695.78 1218.14 1700.78 ;
    END
  END VDD_DIG_ZMEASURE
  PIN D2A_TIA_GAIN[1]
    DIRECTION INPUT ;
    USE SIGNAL ;
    PORT
      LAYER M3 ;
        RECT 782 904.81 782.2 905.11 ;
    END
  END D2A_TIA_GAIN[1]
  PIN D2A_SDM_EN
    DIRECTION INPUT ;
    USE SIGNAL ;
    PORT
      LAYER M3 ;
        RECT 1080.455 1646.7 1080.755 1647 ;
    END
  END D2A_SDM_EN
  PIN D2A_SPARE_TRIM1[2]
    DIRECTION INPUT ;
    USE SIGNAL ;
    PORT
      LAYER M3 ;
        RECT 891.37 1373.585 891.67 1373.885 ;
    END
  END D2A_SPARE_TRIM1[2]
  PIN D2A_PPGDAC1_VSEL[5]
    DIRECTION INPUT ;
    USE SIGNAL ;
    PORT
      LAYER M3 ;
        RECT 782 1108.985 782.3 1109.285 ;
    END
  END D2A_PPGDAC1_VSEL[5]
  PIN D2A_PDVREF_SEL[1]
    DIRECTION INPUT ;
    USE SIGNAL ;
    PORT
      LAYER M3 ;
        RECT 782 898.31 782.2 898.61 ;
    END
  END D2A_PDVREF_SEL[1]
  PIN D2A_PPGDAC0_VSEL[11]
    DIRECTION INPUT ;
    USE SIGNAL ;
    PORT
      LAYER M3 ;
        RECT 782 1133.685 782.3 1133.985 ;
    END
  END D2A_PPGDAC0_VSEL[11]
  PIN D2A_TIA_IDAC[4]
    DIRECTION INPUT ;
    USE SIGNAL ;
    PORT
      LAYER M3 ;
        RECT 782 890.51 782.2 890.81 ;
    END
  END D2A_TIA_IDAC[4]
  PIN D2A_OSC_TRIM[1]
    DIRECTION INPUT ;
    USE SIGNAL ;
    PORT
      LAYER M3 ;
        RECT 699.425 835.925 699.725 836.225 ;
    END
  END D2A_OSC_TRIM[1]
  PIN D2A_ECG_PGA_GSEL[2]
    DIRECTION INPUT ;
    USE SIGNAL ;
    PORT
      LAYER M3 ;
        RECT 1162.255 1646.7 1162.555 1647 ;
    END
  END D2A_ECG_PGA_GSEL[2]
  PIN D2A_TSC_INA_GSEL[0]
    DIRECTION INPUT ;
    USE SIGNAL ;
    PORT
      LAYER M3 ;
        RECT 1217.84 1712.305 1218.14 1712.605 ;
    END
  END D2A_TSC_INA_GSEL[0]
  PIN D2A_OSC_TRIM[3]
    DIRECTION INPUT ;
    USE SIGNAL ;
    PORT
      LAYER M3 ;
        RECT 702.025 835.925 702.325 836.225 ;
    END
  END D2A_OSC_TRIM[3]
  PIN D2A_ATM2
    DIRECTION INPUT ;
    USE SIGNAL ;
    PORT
      LAYER M3 ;
        RECT 782 1180.04 782.3 1180.34 ;
    END
  END D2A_ATM2
  PIN A2D_external_en_I
    DIRECTION OUTPUT ;
    USE SIGNAL ;
    PORT
      LAYER M3 ;
        RECT 525.465 835.925 526.465 836.225 ;
    END
  END A2D_external_en_I
  PIN D2A_OSC_TRIM[2]
    DIRECTION INPUT ;
    USE SIGNAL ;
    PORT
      LAYER M3 ;
        RECT 700.725 835.925 701.025 836.225 ;
    END
  END D2A_OSC_TRIM[2]
  PIN D2A_ATM8
    DIRECTION INPUT ;
    USE SIGNAL ;
    PORT
      LAYER M3 ;
        RECT 782 1170.94 782.3 1171.24 ;
    END
  END D2A_ATM8
  PIN VSSIO2
    DIRECTION INOUT ;
    USE SIGNAL ;
    PORT
      LAYER M3 ;
        RECT 29.91 673.5 48.65 675.5 ;
    END
  END VSSIO2
  PIN VSS2
    DIRECTION INOUT ;
    USE SIGNAL ;
    PORT
      LAYER M3 ;
        RECT 1959.625 2366.34 1961.625 2370.34 ;
    END
  END VSS2
  PIN D2A_PPGDAC0_VSEL[7]
    DIRECTION INPUT ;
    USE SIGNAL ;
    PORT
      LAYER M3 ;
        RECT 782 1128.485 782.3 1128.785 ;
    END
  END D2A_PPGDAC0_VSEL[7]
  PIN D2A_ACLEADOFF_VTHNSEL_TRIM[7]
    DIRECTION INPUT ;
    USE SIGNAL ;
    PORT
      LAYER M3 ;
        RECT 935.235 1464.88 935.535 1465.18 ;
    END
  END D2A_ACLEADOFF_VTHNSEL_TRIM[7]
  PIN D2A_SDM_VIN_SEL[1]
    DIRECTION INPUT ;
    USE SIGNAL ;
    PORT
      LAYER M3 ;
        RECT 1083.055 1646.7 1083.355 1647 ;
    END
  END D2A_SDM_VIN_SEL[1]
  PIN D2A_PPGDAC1_VSEL[1]
    DIRECTION INPUT ;
    USE SIGNAL ;
    PORT
      LAYER M3 ;
        RECT 782 1103.785 782.3 1104.085 ;
    END
  END D2A_PPGDAC1_VSEL[1]
  PIN D2A_ACLEADOFF_CLK
    DIRECTION INPUT ;
    USE SIGNAL ;
    PORT
      LAYER M3 ;
        RECT 1122.855 1646.7 1123.155 1647 ;
    END
  END D2A_ACLEADOFF_CLK
  PIN VSSIO1
    DIRECTION INOUT ;
    USE SIGNAL ;
    PORT
      LAYER M3 ;
        RECT 1959.625 2379.31 1961.625 2398.05 ;
    END
    PORT
      LAYER M3 ;
        RECT 1959.625 2401.35 1961.625 2420.09 ;
    END
  END VSSIO1
  PIN D2A_PPGDAC0_VSEL[0]
    DIRECTION INPUT ;
    USE SIGNAL ;
    PORT
      LAYER M3 ;
        RECT 782 1119.385 782.3 1119.685 ;
    END
  END D2A_PPGDAC0_VSEL[0]
  PIN A2D_VDDI_POR
    DIRECTION OUTPUT ;
    USE SIGNAL ;
    PORT
      LAYER M3 ;
        RECT 519.465 835.925 520.465 836.225 ;
    END
  END A2D_VDDI_POR
  PIN D2A_OSC_ISEL_TRIM[0]
    DIRECTION INPUT ;
    USE SIGNAL ;
    PORT
      LAYER M3 ;
        RECT 736.065 835.925 736.365 836.225 ;
    END
  END D2A_OSC_ISEL_TRIM[0]
  PIN D2A_TIA_GAIN[3]
    DIRECTION INPUT ;
    USE SIGNAL ;
    PORT
      LAYER M3 ;
        RECT 782 902.21 782.2 902.51 ;
    END
  END D2A_TIA_GAIN[3]
  PIN D2A_PPGDAC0_VSEL[10]
    DIRECTION INPUT ;
    USE SIGNAL ;
    PORT
      LAYER M3 ;
        RECT 782 1132.385 782.3 1132.685 ;
    END
  END D2A_PPGDAC0_VSEL[10]
  PIN D2A_BGH_CTRIM[1]
    DIRECTION INPUT ;
    USE SIGNAL ;
    PORT
      LAYER M3 ;
        RECT 707.215 835.925 707.515 836.225 ;
    END
  END D2A_BGH_CTRIM[1]
  PIN D2A_SPARE_TRIM_SW1[7]
    DIRECTION INPUT ;
    USE SIGNAL ;
    PORT
      LAYER M3 ;
        RECT 679.845 835.925 680.145 836.225 ;
    END
  END D2A_SPARE_TRIM_SW1[7]
  PIN A2D_ACLEADOFF_STATN
    DIRECTION OUTPUT ;
    USE SIGNAL ;
    PORT
      LAYER M3 ;
        RECT 1126.455 1646.7 1126.755 1647 ;
    END
  END A2D_ACLEADOFF_STATN
  PIN D2A_ECGCAL_VSEL_TRIM[9]
    DIRECTION INPUT ;
    USE SIGNAL ;
    PORT
      LAYER M3 ;
        RECT 1140.455 1646.7 1140.755 1647 ;
    END
  END D2A_ECGCAL_VSEL_TRIM[9]
  PIN D2A_OSC_TRIM[0]
    DIRECTION INPUT ;
    USE SIGNAL ;
    PORT
      LAYER M3 ;
        RECT 698.125 835.925 698.425 836.225 ;
    END
  END D2A_OSC_TRIM[0]
  PIN A2D_Wake_UP_i
    DIRECTION OUTPUT ;
    USE SIGNAL ;
    PORT
      LAYER M3 ;
        RECT 531.465 835.925 532.465 836.225 ;
    END
  END A2D_Wake_UP_i
  PIN D2A_PPGDAC1_VSEL[8]
    DIRECTION INPUT ;
    USE SIGNAL ;
    PORT
      LAYER M3 ;
        RECT 782 1112.885 782.3 1113.185 ;
    END
  END D2A_PPGDAC1_VSEL[8]
  PIN D2A_TSC_INA_GSEL[1]
    DIRECTION INPUT ;
    USE SIGNAL ;
    PORT
      LAYER M3 ;
        RECT 1217.84 1711.005 1218.14 1711.305 ;
    END
  END D2A_TSC_INA_GSEL[1]
  PIN D2A_SPARE_TRIM2[4]
    DIRECTION INPUT ;
    USE SIGNAL ;
    PORT
      LAYER M3 ;
        RECT 891.37 1365.785 891.67 1366.085 ;
    END
  END D2A_SPARE_TRIM2[4]
  PIN D2A_SPARE_TRIM_SW1[6]
    DIRECTION INPUT ;
    USE SIGNAL ;
    PORT
      LAYER M3 ;
        RECT 681.145 835.925 681.445 836.225 ;
    END
  END D2A_SPARE_TRIM_SW1[6]
  PIN VDD_DIG_AO
    DIRECTION INOUT ;
    USE SIGNAL ;
    PORT
      LAYER M2 ;
        RECT 782 1097.485 782.2 1098.485 ;
    END
    PORT
      LAYER M2 ;
        RECT 723.265 835.925 724.265 836.225 ;
    END
    PORT
      LAYER M2 ;
        RECT 693.245 835.925 694.245 836.225 ;
    END
    PORT
      LAYER M2 ;
        RECT 558.465 835.925 559.465 836.225 ;
    END
    PORT
      LAYER M2 ;
        RECT 470.87 835.925 471.87 836.225 ;
    END
    PORT
      LAYER M2 ;
        RECT 782 1155.215 782.3 1156.215 ;
    END
    PORT
      LAYER M2 ;
        RECT 782 873.21 782.2 874.21 ;
    END
    PORT
      LAYER M2 ;
        RECT 782 922.31 782.3 923.31 ;
    END
    PORT
      LAYER M2 ;
        RECT 1217.84 1669.005 1218.14 1670.005 ;
    END
    PORT
      LAYER M5 ;
        RECT 220 835.925 240 836.225 ;
    END
    PORT
      LAYER M2 ;
        RECT 891.37 1330.895 891.67 1331.895 ;
    END
    PORT
      LAYER M2 ;
        RECT 891.37 1384.375 891.67 1385.375 ;
    END
    PORT
      LAYER M2 ;
        RECT 891.37 1358.66 891.67 1359.66 ;
    END
    PORT
      LAYER M2 ;
        RECT 1166.555 1646.7 1167.555 1647 ;
    END
    PORT
      LAYER M2 ;
        RECT 1217.84 1716.655 1218.14 1717.655 ;
    END
    PORT
      LAYER M2 ;
        RECT 983.735 1464.88 984.735 1465.18 ;
    END
    PORT
      LAYER M2 ;
        RECT 925.735 1464.88 926.735 1465.18 ;
    END
    PORT
      LAYER M2 ;
        RECT 782 1136.835 782.3 1137.835 ;
    END
    PORT
      LAYER M2 ;
        RECT 782 1187.54 782.3 1188.54 ;
    END
    PORT
      LAYER M2 ;
        RECT 1070.26 1646.7 1071.26 1647 ;
    END
  END VDD_DIG_AO
  PIN A2D_LOFF_STATN
    DIRECTION OUTPUT ;
    USE SIGNAL ;
    PORT
      LAYER M3 ;
        RECT 1107.855 1646.7 1108.155 1647 ;
    END
  END A2D_LOFF_STATN
  PIN D2A_PPGDAC1_VSEL[4]
    DIRECTION INPUT ;
    USE SIGNAL ;
    PORT
      LAYER M3 ;
        RECT 782 1107.685 782.3 1107.985 ;
    END
  END D2A_PPGDAC1_VSEL[4]
  PIN A2D_OSC_OUT
    DIRECTION OUTPUT ;
    USE SIGNAL ;
    PORT
      LAYER M3 ;
        RECT 715.31 835.925 716.31 836.225 ;
    END
  END A2D_OSC_OUT
  PIN D2A_LEDDAC_SEL
    DIRECTION INPUT ;
    USE SIGNAL ;
    PORT
      LAYER M3 ;
        RECT 782 912.61 782.2 912.91 ;
    END
  END D2A_LEDDAC_SEL
  PIN D2A_SW_Z_DDS[0]
    DIRECTION INPUT ;
    USE SIGNAL ;
    PORT
      LAYER M3 ;
        RECT 1217.84 1689.58 1218.14 1689.88 ;
    END
  END D2A_SW_Z_DDS[0]
  PIN D2A_TSC_BJT_SEL[1]
    DIRECTION INPUT ;
    USE SIGNAL ;
    PORT
      LAYER M3 ;
        RECT 1217.84 1704.505 1218.14 1704.805 ;
    END
  END D2A_TSC_BJT_SEL[1]
  PIN D2A_ECG_DDACHOP_EN
    DIRECTION INPUT ;
    USE SIGNAL ;
    PORT
      LAYER M3 ;
        RECT 1153.155 1646.7 1153.455 1647 ;
    END
  END D2A_ECG_DDACHOP_EN
  PIN D2A_RLD_CLK64K
    DIRECTION INPUT ;
    USE SIGNAL ;
    PORT
      LAYER M3 ;
        RECT 1091.555 1646.7 1091.855 1647 ;
    END
  END D2A_RLD_CLK64K
  PIN D2A_SDM_BIAS[1]
    DIRECTION INPUT ;
    USE SIGNAL ;
    PORT
      LAYER M3 ;
        RECT 1079.155 1646.7 1079.455 1647 ;
    END
  END D2A_SDM_BIAS[1]
  PIN D2A_SDM_VIN_SEL[2]
    DIRECTION INPUT ;
    USE SIGNAL ;
    PORT
      LAYER M3 ;
        RECT 1084.355 1646.7 1084.655 1647 ;
    END
  END D2A_SDM_VIN_SEL[2]
  PIN D2A_OSC_TRIM[5]
    DIRECTION INPUT ;
    USE SIGNAL ;
    PORT
      LAYER M3 ;
        RECT 704.625 835.925 704.925 836.225 ;
    END
  END D2A_OSC_TRIM[5]
  PIN D2A_ACLEADOFF_VTHPSEL_TRIM[7]
    DIRECTION INPUT ;
    USE SIGNAL ;
    PORT
      LAYER M3 ;
        RECT 928.735 1464.88 929.035 1465.18 ;
    END
  END D2A_ACLEADOFF_VTHPSEL_TRIM[7]
  PIN D2A_DCLEADOFF_ISEL_TRIM[4]
    DIRECTION INPUT ;
    USE SIGNAL ;
    PORT
      LAYER M3 ;
        RECT 959.935 1464.88 960.235 1465.18 ;
    END
  END D2A_DCLEADOFF_ISEL_TRIM[4]
  PIN D2A_SPARE_TRIM2[0]
    DIRECTION INPUT ;
    USE SIGNAL ;
    PORT
      LAYER M3 ;
        RECT 891.37 1360.585 891.67 1360.885 ;
    END
  END D2A_SPARE_TRIM2[0]
  PIN D2A_ECGCAL_VSEL_TRIM[1]
    DIRECTION INPUT ;
    USE SIGNAL ;
    PORT
      LAYER M3 ;
        RECT 1130.055 1646.7 1130.355 1647 ;
    END
  END D2A_ECGCAL_VSEL_TRIM[1]
  PIN D2A_PPG_TEST_IN[1]
    DIRECTION INPUT ;
    USE SIGNAL ;
    PORT
      LAYER M3 ;
        RECT 782 884.01 782.2 884.31 ;
    END
  END D2A_PPG_TEST_IN[1]
  PIN D2A_PPGDAC1_VSEL[10]
    DIRECTION INPUT ;
    USE SIGNAL ;
    PORT
      LAYER M3 ;
        RECT 782 1115.485 782.3 1115.785 ;
    END
  END D2A_PPGDAC1_VSEL[10]
  PIN D2A_PPG_SH_CK
    DIRECTION INPUT ;
    USE SIGNAL ;
    PORT
      LAYER M3 ;
        RECT 782 880.11 782.2 880.41 ;
    END
  END D2A_PPG_SH_CK
  PIN D2A_SW_Z_CALMD
    DIRECTION INPUT ;
    USE SIGNAL ;
    PORT
      LAYER M3 ;
        RECT 1217.84 1690.88 1218.14 1691.18 ;
    END
  END D2A_SW_Z_CALMD
  PIN D2A_ATM0
    DIRECTION INPUT ;
    USE SIGNAL ;
    PORT
      LAYER M3 ;
        RECT 782 1182.64 782.3 1182.94 ;
    END
  END D2A_ATM0
  PIN D2A_PPGDAC0_VSEL[2]
    DIRECTION INPUT ;
    USE SIGNAL ;
    PORT
      LAYER M3 ;
        RECT 782 1121.985 782.3 1122.285 ;
    END
  END D2A_PPGDAC0_VSEL[2]
  PIN D2A_SW_Z_DDS[2]
    DIRECTION INPUT ;
    USE SIGNAL ;
    PORT
      LAYER M3 ;
        RECT 1217.84 1686.98 1218.14 1687.28 ;
    END
  END D2A_SW_Z_DDS[2]
  PIN D2A_OSC_TRIM[4]
    DIRECTION INPUT ;
    USE SIGNAL ;
    PORT
      LAYER M3 ;
        RECT 703.325 835.925 703.625 836.225 ;
    END
  END D2A_OSC_TRIM[4]
  PIN D2A_LEDSEL[1]
    DIRECTION INPUT ;
    USE SIGNAL ;
    PORT
      LAYER M3 ;
        RECT 782 910.01 782.2 910.31 ;
    END
  END D2A_LEDSEL[1]
  PIN D2A_PPGDAC0_VSEL[4]
    DIRECTION INPUT ;
    USE SIGNAL ;
    PORT
      LAYER M3 ;
        RECT 782 1124.585 782.3 1124.885 ;
    END
  END D2A_PPGDAC0_VSEL[4]
  PIN D2A_PPGDAC0_VSEL[3]
    DIRECTION INPUT ;
    USE SIGNAL ;
    PORT
      LAYER M3 ;
        RECT 782 1123.285 782.3 1123.585 ;
    END
  END D2A_PPGDAC0_VSEL[3]
  PIN A2D_ACLEADOFF_STATP
    DIRECTION OUTPUT ;
    USE SIGNAL ;
    PORT
      LAYER M3 ;
        RECT 1125.155 1646.7 1125.455 1647 ;
    END
  END A2D_ACLEADOFF_STATP
  PIN D2A_RLD_CHOP_EN
    DIRECTION INPUT ;
    USE SIGNAL ;
    PORT
      LAYER M3 ;
        RECT 1089.255 1646.7 1089.555 1647 ;
    END
  END D2A_RLD_CHOP_EN
  PIN D2A_PPGDAC0_EN
    DIRECTION INPUT ;
    USE SIGNAL ;
    PORT
      LAYER M3 ;
        RECT 782 1134.985 782.3 1135.285 ;
    END
  END D2A_PPGDAC0_EN
  PIN D2A_PPGDAC1_VSEL[2]
    DIRECTION INPUT ;
    USE SIGNAL ;
    PORT
      LAYER M3 ;
        RECT 782 1105.085 782.3 1105.385 ;
    END
  END D2A_PPGDAC1_VSEL[2]
  PIN D2A_ACLEADOFF_ISEL_TRIM[0]
    DIRECTION INPUT ;
    USE SIGNAL ;
    PORT
      LAYER M3 ;
        RECT 1117.955 1646.7 1118.255 1647 ;
    END
  END D2A_ACLEADOFF_ISEL_TRIM[0]
  PIN D2A_EN_TIA_VREFBUFFER
    DIRECTION INPUT ;
    USE SIGNAL ;
    PORT
      LAYER M3 ;
        RECT 782 897.01 782.2 897.31 ;
    END
  END D2A_EN_TIA_VREFBUFFER
  PIN D2A_SPARE_TRIM1[6]
    DIRECTION INPUT ;
    USE SIGNAL ;
    PORT
      LAYER M3 ;
        RECT 891.37 1378.785 891.67 1379.085 ;
    END
  END D2A_SPARE_TRIM1[6]
  PIN A2D_SPARE_TRIM_SW0[3]
    DIRECTION OUTPUT ;
    USE SIGNAL ;
    PORT
      LAYER M3 ;
        RECT 891.37 1342.39 891.67 1343.39 ;
    END
  END A2D_SPARE_TRIM_SW0[3]
  PIN D2A_ECG_DDA_GSEL[2]
    DIRECTION INPUT ;
    USE SIGNAL ;
    PORT
      LAYER M3 ;
        RECT 1151.855 1646.7 1152.155 1647 ;
    END
  END D2A_ECG_DDA_GSEL[2]
  PIN D2A_TSC_BJT_SEL[2]
    DIRECTION INPUT ;
    USE SIGNAL ;
    PORT
      LAYER M3 ;
        RECT 1217.84 1702.78 1218.14 1703.08 ;
    END
  END D2A_TSC_BJT_SEL[2]
  PIN A2D_SPARE_TRIM_SW0[6]
    DIRECTION OUTPUT ;
    USE SIGNAL ;
    PORT
      LAYER M3 ;
        RECT 891.37 1351.39 891.67 1352.39 ;
    END
  END A2D_SPARE_TRIM_SW0[6]
  PIN D2A_ECGCAL_VSEL_TRIM[3]
    DIRECTION INPUT ;
    USE SIGNAL ;
    PORT
      LAYER M3 ;
        RECT 1132.655 1646.7 1132.955 1647 ;
    END
  END D2A_ECGCAL_VSEL_TRIM[3]
  PIN D2A_SPARE_TRIM0[1]
    DIRECTION INPUT ;
    USE SIGNAL ;
    PORT
      LAYER M3 ;
        RECT 971.635 1464.88 971.935 1465.18 ;
    END
  END D2A_SPARE_TRIM0[1]
  PIN D2A_PPGDAC0_VSEL[8]
    DIRECTION INPUT ;
    USE SIGNAL ;
    PORT
      LAYER M3 ;
        RECT 782 1129.785 782.3 1130.085 ;
    END
  END D2A_PPGDAC0_VSEL[8]
  PIN A2D_SDM_OUT
    DIRECTION OUTPUT ;
    USE SIGNAL ;
    PORT
      LAYER M3 ;
        RECT 1073.26 1646.7 1073.56 1647 ;
    END
  END A2D_SDM_OUT
  PIN D2A_ATM5
    DIRECTION INPUT ;
    USE SIGNAL ;
    PORT
      LAYER M3 ;
        RECT 782 1176.14 782.3 1176.44 ;
    END
  END D2A_ATM5
  PIN D2A_SW_Z_DDS[1]
    DIRECTION INPUT ;
    USE SIGNAL ;
    PORT
      LAYER M3 ;
        RECT 1217.84 1688.28 1218.14 1688.58 ;
    END
  END D2A_SW_Z_DDS[1]
  PIN D2A_ATM4
    DIRECTION INPUT ;
    USE SIGNAL ;
    PORT
      LAYER M3 ;
        RECT 782 1177.44 782.3 1177.74 ;
    END
  END D2A_ATM4
  PIN A2D_LOFF_STATP
    DIRECTION OUTPUT ;
    USE SIGNAL ;
    PORT
      LAYER M3 ;
        RECT 1106.555 1646.7 1106.855 1647 ;
    END
  END A2D_LOFF_STATP
  PIN D2A_SPARE_TRIM_SW1[4]
    DIRECTION INPUT ;
    USE SIGNAL ;
    PORT
      LAYER M3 ;
        RECT 683.745 835.925 684.045 836.225 ;
    END
  END D2A_SPARE_TRIM_SW1[4]
  PIN D2A_ACLEADOFF_VTHNSEL_TRIM[0]
    DIRECTION INPUT ;
    USE SIGNAL ;
    PORT
      LAYER M3 ;
        RECT 1114.055 1646.7 1114.355 1647 ;
    END
  END D2A_ACLEADOFF_VTHNSEL_TRIM[0]
  PIN D2A_2ELECTRODE_EN
    DIRECTION INPUT ;
    USE SIGNAL ;
    PORT
      LAYER M3 ;
        RECT 1087.955 1646.7 1088.255 1647 ;
    END
  END D2A_2ELECTRODE_EN
  PIN D2A_ATM12
    DIRECTION INPUT ;
    USE SIGNAL ;
    PORT
      LAYER M3 ;
        RECT 782 1165.74 782.3 1166.04 ;
    END
  END D2A_ATM12
  PIN D2A_OSC_ISEL_TRIM[6]
    DIRECTION INPUT ;
    USE SIGNAL ;
    PORT
      LAYER M3 ;
        RECT 728.265 835.925 728.565 836.225 ;
    END
  END D2A_OSC_ISEL_TRIM[6]
  PIN D2A_OSC_ISEL_TRIM[5]
    DIRECTION INPUT ;
    USE SIGNAL ;
    PORT
      LAYER M3 ;
        RECT 729.565 835.925 729.865 836.225 ;
    END
  END D2A_OSC_ISEL_TRIM[5]
  PIN D2A_OSC_ISEL_TRIM[4]
    DIRECTION INPUT ;
    USE SIGNAL ;
    PORT
      LAYER M3 ;
        RECT 730.865 835.925 731.165 836.225 ;
    END
  END D2A_OSC_ISEL_TRIM[4]
  PIN D2A_OSC_ISEL_TRIM[3]
    DIRECTION INPUT ;
    USE SIGNAL ;
    PORT
      LAYER M3 ;
        RECT 732.165 835.925 732.465 836.225 ;
    END
  END D2A_OSC_ISEL_TRIM[3]
  PIN D2A_OSC_ISEL_TRIM[2]
    DIRECTION INPUT ;
    USE SIGNAL ;
    PORT
      LAYER M3 ;
        RECT 733.465 835.925 733.765 836.225 ;
    END
  END D2A_OSC_ISEL_TRIM[2]
  PIN D2A_ECGCAL_VSEL_TRIM[8]
    DIRECTION INPUT ;
    USE SIGNAL ;
    PORT
      LAYER M3 ;
        RECT 1139.155 1646.7 1139.455 1647 ;
    END
  END D2A_ECGCAL_VSEL_TRIM[8]
  PIN D2A_ECGCAL_VSEL_TRIM[7]
    DIRECTION INPUT ;
    USE SIGNAL ;
    PORT
      LAYER M3 ;
        RECT 1137.855 1646.7 1138.155 1647 ;
    END
  END D2A_ECGCAL_VSEL_TRIM[7]
  PIN D2A_ECGCAL_VSEL_TRIM[6]
    DIRECTION INPUT ;
    USE SIGNAL ;
    PORT
      LAYER M3 ;
        RECT 1136.555 1646.7 1136.855 1647 ;
    END
  END D2A_ECGCAL_VSEL_TRIM[6]
  PIN D2A_SPARE_TRIM_SW0[2]
    DIRECTION INPUT ;
    USE SIGNAL ;
    PORT
      LAYER M3 ;
        RECT 782 1195.14 782.3 1195.44 ;
    END
  END D2A_SPARE_TRIM_SW0[2]
  PIN D2A_ACLEADOFF_ISEL_TRIM[6]
    DIRECTION INPUT ;
    USE SIGNAL ;
    PORT
      LAYER M3 ;
        RECT 943.035 1464.88 943.335 1465.18 ;
    END
  END D2A_ACLEADOFF_ISEL_TRIM[6]
  PIN VDD_DIG_AFSW
    DIRECTION INOUT ;
    USE SIGNAL ;
    PORT
      LAYER M5 ;
        RECT 245 835.925 265 836.225 ;
    END
  END VDD_DIG_AFSW
  PIN D2A_ACLEADOFF_VTHNSEL_TRIM[3]
    DIRECTION INPUT ;
    USE SIGNAL ;
    PORT
      LAYER M3 ;
        RECT 940.435 1464.88 940.735 1465.18 ;
    END
  END D2A_ACLEADOFF_VTHNSEL_TRIM[3]
  PIN D2A_ACLEADOFF_VTHNSEL_TRIM[4]
    DIRECTION INPUT ;
    USE SIGNAL ;
    PORT
      LAYER M3 ;
        RECT 939.135 1464.88 939.435 1465.18 ;
    END
  END D2A_ACLEADOFF_VTHNSEL_TRIM[4]
  PIN D2A_ACLEADOFF_VTHNSEL_TRIM[6]
    DIRECTION INPUT ;
    USE SIGNAL ;
    PORT
      LAYER M3 ;
        RECT 936.535 1464.88 936.835 1465.18 ;
    END
  END D2A_ACLEADOFF_VTHNSEL_TRIM[6]
  PIN D2A_ACLEADOFF_VTHPSEL_TRIM[4]
    DIRECTION INPUT ;
    USE SIGNAL ;
    PORT
      LAYER M3 ;
        RECT 932.635 1464.88 932.935 1465.18 ;
    END
  END D2A_ACLEADOFF_VTHPSEL_TRIM[4]
  PIN D2A_ACLEADOFF_VTHPSEL_TRIM[5]
    DIRECTION INPUT ;
    USE SIGNAL ;
    PORT
      LAYER M3 ;
        RECT 931.335 1464.88 931.635 1465.18 ;
    END
  END D2A_ACLEADOFF_VTHPSEL_TRIM[5]
  PIN D2A_ACLEADOFF_VTHPSEL_TRIM[6]
    DIRECTION INPUT ;
    USE SIGNAL ;
    PORT
      LAYER M3 ;
        RECT 930.035 1464.88 930.335 1465.18 ;
    END
  END D2A_ACLEADOFF_VTHPSEL_TRIM[6]
  PIN D2A_DCLEADOFF_COMP_TH_TRIM[2]
    DIRECTION INPUT ;
    USE SIGNAL ;
    PORT
      LAYER M3 ;
        RECT 1104.25 1646.7 1104.55 1647 ;
    END
  END D2A_DCLEADOFF_COMP_TH_TRIM[2]
  PIN D2A_DCLEADOFF_COMP_TH_TRIM[1]
    DIRECTION INPUT ;
    USE SIGNAL ;
    PORT
      LAYER M3 ;
        RECT 1102.95 1646.7 1103.25 1647 ;
    END
  END D2A_DCLEADOFF_COMP_TH_TRIM[1]
  PIN D2A_DCLEADOFF_COMP_TH_TRIM[0]
    DIRECTION INPUT ;
    USE SIGNAL ;
    PORT
      LAYER M3 ;
        RECT 1101.65 1646.7 1101.95 1647 ;
    END
  END D2A_DCLEADOFF_COMP_TH_TRIM[0]
  PIN D2A_DCLEADOFF_ISEL_TRIM[2]
    DIRECTION INPUT ;
    USE SIGNAL ;
    PORT
      LAYER M3 ;
        RECT 1099.05 1646.7 1099.35 1647 ;
    END
  END D2A_DCLEADOFF_ISEL_TRIM[2]
  PIN D2A_DCLEADOFF_ISEL_TRIM[0]
    DIRECTION INPUT ;
    USE SIGNAL ;
    PORT
      LAYER M3 ;
        RECT 1096.45 1646.7 1096.75 1647 ;
    END
  END D2A_DCLEADOFF_ISEL_TRIM[0]
  PIN VDD_DIG_SW
    DIRECTION INOUT ;
    USE SIGNAL ;
    PORT
      LAYER M3 ;
        RECT 549.465 835.925 554.465 836.225 ;
    END
  END VDD_DIG_SW
  PIN D2A_LDO1V5_VTRIM[2]
    DIRECTION INPUT ;
    USE SIGNAL ;
    PORT
      LAYER M3 ;
        RECT 476.57 835.925 476.87 836.225 ;
    END
  END D2A_LDO1V5_VTRIM[2]
  PIN D2A_LDO1V5_VTRIM[3]
    DIRECTION INPUT ;
    USE SIGNAL ;
    PORT
      LAYER M3 ;
        RECT 477.87 835.925 478.17 836.225 ;
    END
  END D2A_LDO1V5_VTRIM[3]
  PIN D2A_ACLEADOFF_VTHPSEL_TRIM[3]
    DIRECTION INPUT ;
    USE SIGNAL ;
    PORT
      LAYER M3 ;
        RECT 933.935 1464.88 934.235 1465.18 ;
    END
  END D2A_ACLEADOFF_VTHPSEL_TRIM[3]
  PIN D2A_LDO1V5_VTRIM[5]
    DIRECTION INPUT ;
    USE SIGNAL ;
    PORT
      LAYER M3 ;
        RECT 480.47 835.925 480.77 836.225 ;
    END
  END D2A_LDO1V5_VTRIM[5]
  PIN D2A_LDO1V5_VTRIM[6]
    DIRECTION INPUT ;
    USE SIGNAL ;
    PORT
      LAYER M3 ;
        RECT 481.77 835.925 482.07 836.225 ;
    END
  END D2A_LDO1V5_VTRIM[6]
  PIN D2A_LDO1V5_VTRIM[7]
    DIRECTION INPUT ;
    USE SIGNAL ;
    PORT
      LAYER M3 ;
        RECT 483.07 835.925 483.37 836.225 ;
    END
  END D2A_LDO1V5_VTRIM[7]
  PIN D2A_SPARE_TRIM2[7]
    DIRECTION INPUT ;
    USE SIGNAL ;
    PORT
      LAYER M3 ;
        RECT 891.37 1369.685 891.67 1369.985 ;
    END
  END D2A_SPARE_TRIM2[7]
  PIN D2A_SPARE_TRIM_SW0[0]
    DIRECTION INPUT ;
    USE SIGNAL ;
    PORT
      LAYER M3 ;
        RECT 782 1192.54 782.3 1192.84 ;
    END
  END D2A_SPARE_TRIM_SW0[0]
  PIN D2A_SPARE_TRIM_SW0[3]
    DIRECTION INPUT ;
    USE SIGNAL ;
    PORT
      LAYER M3 ;
        RECT 782 1196.44 782.3 1196.74 ;
    END
  END D2A_SPARE_TRIM_SW0[3]
  PIN D2A_SPARE_TRIM_SW0[4]
    DIRECTION INPUT ;
    USE SIGNAL ;
    PORT
      LAYER M3 ;
        RECT 782 1197.74 782.3 1198.04 ;
    END
  END D2A_SPARE_TRIM_SW0[4]
  PIN D2A_SPARE_TRIM_SW0[5]
    DIRECTION INPUT ;
    USE SIGNAL ;
    PORT
      LAYER M3 ;
        RECT 782 1199.04 782.3 1199.34 ;
    END
  END D2A_SPARE_TRIM_SW0[5]
  PIN D2A_SPARE_TRIM_SW0[6]
    DIRECTION INPUT ;
    USE SIGNAL ;
    PORT
      LAYER M3 ;
        RECT 782 1200.34 782.3 1200.64 ;
    END
  END D2A_SPARE_TRIM_SW0[6]
  PIN D2A_SPARE_TRIM_SW0[7]
    DIRECTION INPUT ;
    USE SIGNAL ;
    PORT
      LAYER M3 ;
        RECT 782 1201.64 782.3 1201.94 ;
    END
  END D2A_SPARE_TRIM_SW0[7]
  PIN D2A_SPARE_TRIM3[0]
    DIRECTION INPUT ;
    USE SIGNAL ;
    PORT
      LAYER M3 ;
        RECT 782 925.31 782.3 925.61 ;
    END
  END D2A_SPARE_TRIM3[0]
  PIN D2A_PPGDAC1_VSEL[7]
    DIRECTION INPUT ;
    USE SIGNAL ;
    PORT
      LAYER M3 ;
        RECT 782 1111.585 782.3 1111.885 ;
    END
  END D2A_PPGDAC1_VSEL[7]
  PIN A2D_SPARE_TRIM_SW0[0]
    DIRECTION OUTPUT ;
    USE SIGNAL ;
    PORT
      LAYER M3 ;
        RECT 891.37 1333.39 891.67 1334.39 ;
    END
  END A2D_SPARE_TRIM_SW0[0]
  PIN D2A_SPARE_TRIM1[0]
    DIRECTION INPUT ;
    USE SIGNAL ;
    PORT
      LAYER M3 ;
        RECT 891.37 1370.985 891.67 1371.285 ;
    END
  END D2A_SPARE_TRIM1[0]
  PIN D2A_SPARE_TRIM1[1]
    DIRECTION INPUT ;
    USE SIGNAL ;
    PORT
      LAYER M3 ;
        RECT 891.37 1372.285 891.67 1372.585 ;
    END
  END D2A_SPARE_TRIM1[1]
  PIN D2A_SPARE_TRIM1[5]
    DIRECTION INPUT ;
    USE SIGNAL ;
    PORT
      LAYER M3 ;
        RECT 891.37 1377.485 891.67 1377.785 ;
    END
  END D2A_SPARE_TRIM1[5]
  PIN POC
    DIRECTION OUTPUT ;
    USE POWER ;
    PORT
      LAYER M3 ;
        RECT 537.465 835.925 538.465 836.225 ;
    END
  END POC
  PIN D2A_ECGCAL_VSEL_TRIM[4]
    DIRECTION INPUT ;
    USE SIGNAL ;
    PORT
      LAYER M3 ;
        RECT 1133.955 1646.7 1134.255 1647 ;
    END
  END D2A_ECGCAL_VSEL_TRIM[4]
  PIN D2A_DCLEADOFF_EN
    DIRECTION INPUT ;
    USE SIGNAL ;
    PORT
      LAYER M3 ;
        RECT 1100.35 1646.7 1100.65 1647 ;
    END
  END D2A_DCLEADOFF_EN
  PIN D2A_BGH_CTRIM[6]
    DIRECTION INPUT ;
    USE SIGNAL ;
    PORT
      LAYER M3 ;
        RECT 713.715 835.925 714.015 836.225 ;
    END
  END D2A_BGH_CTRIM[6]
  PIN D2A_BGH_CTRIM[4]
    DIRECTION INPUT ;
    USE SIGNAL ;
    PORT
      LAYER M3 ;
        RECT 711.115 835.925 711.415 836.225 ;
    END
  END D2A_BGH_CTRIM[4]
  PIN D2A_BGH_CTRIM[3]
    DIRECTION INPUT ;
    USE SIGNAL ;
    PORT
      LAYER M3 ;
        RECT 709.815 835.925 710.115 836.225 ;
    END
  END D2A_BGH_CTRIM[3]
  PIN D2A_BGH_CTRIM[2]
    DIRECTION INPUT ;
    USE SIGNAL ;
    PORT
      LAYER M3 ;
        RECT 708.515 835.925 708.815 836.225 ;
    END
  END D2A_BGH_CTRIM[2]
  PIN D2A_BGH_CTRIM[5]
    DIRECTION INPUT ;
    USE SIGNAL ;
    PORT
      LAYER M3 ;
        RECT 712.415 835.925 712.715 836.225 ;
    END
  END D2A_BGH_CTRIM[5]
  PIN D2A_ECGCAL_VSEL_TRIM[0]
    DIRECTION INPUT ;
    USE SIGNAL ;
    PORT
      LAYER M3 ;
        RECT 1128.755 1646.7 1129.055 1647 ;
    END
  END D2A_ECGCAL_VSEL_TRIM[0]
  PIN D2A_BG1P2_BUF_EN
    DIRECTION INPUT ;
    USE SIGNAL ;
    PORT
      LAYER M3 ;
        RECT 782 1185.24 782.3 1185.54 ;
    END
  END D2A_BG1P2_BUF_EN
  PIN D2A_SPARE_TRIM_SW1[0]
    DIRECTION INPUT ;
    USE SIGNAL ;
    PORT
      LAYER M3 ;
        RECT 688.945 835.925 689.245 836.225 ;
    END
  END D2A_SPARE_TRIM_SW1[0]
  PIN D2A_TIA_IDAC[5]
    DIRECTION INPUT ;
    USE SIGNAL ;
    PORT
      LAYER M3 ;
        RECT 782 889.21 782.2 889.51 ;
    END
  END D2A_TIA_IDAC[5]
  PIN D2A_ACLEADOFF_VTHPSEL_TRIM[0]
    DIRECTION INPUT ;
    USE SIGNAL ;
    PORT
      LAYER M3 ;
        RECT 1110.155 1646.7 1110.455 1647 ;
    END
  END D2A_ACLEADOFF_VTHPSEL_TRIM[0]
  PIN D2A_ECG_DDA_GSEL[0]
    DIRECTION INPUT ;
    USE SIGNAL ;
    PORT
      LAYER M3 ;
        RECT 1144.055 1646.7 1144.355 1647 ;
    END
  END D2A_ECG_DDA_GSEL[0]
  PIN A2D_SPARE_TRIM_SW0[4]
    DIRECTION OUTPUT ;
    USE SIGNAL ;
    PORT
      LAYER M3 ;
        RECT 891.37 1345.39 891.67 1346.39 ;
    END
  END A2D_SPARE_TRIM_SW0[4]
  PIN D2A_LEDSEL[0]
    DIRECTION INPUT ;
    USE SIGNAL ;
    PORT
      LAYER M3 ;
        RECT 782 911.31 782.2 911.61 ;
    END
  END D2A_LEDSEL[0]
  PIN D2A_SPARE_TRIM1[3]
    DIRECTION INPUT ;
    USE SIGNAL ;
    PORT
      LAYER M3 ;
        RECT 891.37 1374.885 891.67 1375.185 ;
    END
  END D2A_SPARE_TRIM1[3]
  PIN D2A_BGH_VTRIM[2]
    DIRECTION INPUT ;
    USE SIGNAL ;
    PORT
      LAYER M3 ;
        RECT 490.755 835.925 491.055 836.225 ;
    END
  END D2A_BGH_VTRIM[2]
  PIN D2A_ACLEADOFF_VTHNSEL_TRIM[5]
    DIRECTION INPUT ;
    USE SIGNAL ;
    PORT
      LAYER M3 ;
        RECT 937.835 1464.88 938.135 1465.18 ;
    END
  END D2A_ACLEADOFF_VTHNSEL_TRIM[5]
  PIN D2A_SDM_VIN_SEL[0]
    DIRECTION INPUT ;
    USE SIGNAL ;
    PORT
      LAYER M3 ;
        RECT 1081.755 1646.7 1082.055 1647 ;
    END
  END D2A_SDM_VIN_SEL[0]
  PIN D2A_ACLEADOFF_VTHNSEL_TRIM[2]
    DIRECTION INPUT ;
    USE SIGNAL ;
    PORT
      LAYER M3 ;
        RECT 1116.655 1646.7 1116.955 1647 ;
    END
  END D2A_ACLEADOFF_VTHNSEL_TRIM[2]
  PIN D2A_ATM7
    DIRECTION INPUT ;
    USE SIGNAL ;
    PORT
      LAYER M3 ;
        RECT 782 1172.24 782.3 1172.54 ;
    END
  END D2A_ATM7
  PIN D2A_BGH_VTRIM[6]
    DIRECTION INPUT ;
    USE SIGNAL ;
    PORT
      LAYER M3 ;
        RECT 485.555 835.925 485.855 836.225 ;
    END
  END D2A_BGH_VTRIM[6]
  PIN D2A_ACLEADOFF_ISEL_TRIM[4]
    DIRECTION INPUT ;
    USE SIGNAL ;
    PORT
      LAYER M3 ;
        RECT 945.635 1464.88 945.935 1465.18 ;
    END
  END D2A_ACLEADOFF_ISEL_TRIM[4]
  PIN D2A_PDVREF_SEL[0]
    DIRECTION INPUT ;
    USE SIGNAL ;
    PORT
      LAYER M3 ;
        RECT 782 899.61 782.2 899.91 ;
    END
  END D2A_PDVREF_SEL[0]
  PIN D2A_SPARE_TRIM0[2]
    DIRECTION INPUT ;
    USE SIGNAL ;
    PORT
      LAYER M3 ;
        RECT 972.935 1464.88 973.235 1465.18 ;
    END
  END D2A_SPARE_TRIM0[2]
  PIN D2A_EN_PPG_SH
    DIRECTION INPUT ;
    USE SIGNAL ;
    PORT
      LAYER M3 ;
        RECT 782 881.41 782.2 881.71 ;
    END
  END D2A_EN_PPG_SH
  PIN VDDIO
    DIRECTION INOUT ;
    USE SIGNAL ;
    PORT
      LAYER M3 ;
        RECT 281.4 835.925 286.4 836.225 ;
    END
  END VDDIO
  PIN D2A_SPARE_TRIM3[1]
    DIRECTION INPUT ;
    USE SIGNAL ;
    PORT
      LAYER M3 ;
        RECT 782 926.61 782.3 926.91 ;
    END
  END D2A_SPARE_TRIM3[1]
  PIN D2A_PPGDAC1_EN
    DIRECTION INPUT ;
    USE SIGNAL ;
    PORT
      LAYER M3 ;
        RECT 782 1118.085 782.3 1118.385 ;
    END
  END D2A_PPGDAC1_EN
  PIN D2A_PPG_TEST_OUT[1]
    DIRECTION INPUT ;
    USE SIGNAL ;
    PORT
      LAYER M3 ;
        RECT 782 877.51 782.2 877.81 ;
    END
  END D2A_PPG_TEST_OUT[1]
  PIN D2A_ATM9
    DIRECTION INPUT ;
    USE SIGNAL ;
    PORT
      LAYER M3 ;
        RECT 782 1169.64 782.3 1169.94 ;
    END
  END D2A_ATM9
  PIN D2A_TSC_BJT_SEL[0]
    DIRECTION INPUT ;
    USE SIGNAL ;
    PORT
      LAYER M3 ;
        RECT 1217.84 1705.805 1218.14 1706.105 ;
    END
  END D2A_TSC_BJT_SEL[0]
  PIN D2A_SPARE_TRIM3[7]
    DIRECTION INPUT ;
    USE SIGNAL ;
    PORT
      LAYER M3 ;
        RECT 782 934.41 782.3 934.71 ;
    END
  END D2A_SPARE_TRIM3[7]
  PIN D2A_TSC_INA_GSEL[2]
    DIRECTION INPUT ;
    USE SIGNAL ;
    PORT
      LAYER M3 ;
        RECT 1217.84 1709.705 1218.14 1710.005 ;
    END
  END D2A_TSC_INA_GSEL[2]
  PIN D2A_ACLEADOFF_ISEL_TRIM[5]
    DIRECTION INPUT ;
    USE SIGNAL ;
    PORT
      LAYER M3 ;
        RECT 944.335 1464.88 944.635 1465.18 ;
    END
  END D2A_ACLEADOFF_ISEL_TRIM[5]
  PIN D2A_PPGDAC1_VSEL[0]
    DIRECTION INPUT ;
    USE SIGNAL ;
    PORT
      LAYER M3 ;
        RECT 782 1102.485 782.3 1102.785 ;
    END
  END D2A_PPGDAC1_VSEL[0]
  PIN D2A_OSC_ISEL_TRIM[7]
    DIRECTION INPUT ;
    USE SIGNAL ;
    PORT
      LAYER M3 ;
        RECT 726.965 835.925 727.265 836.225 ;
    END
  END D2A_OSC_ISEL_TRIM[7]
  PIN D2A_BIST_ISEL[0]
    DIRECTION INPUT ;
    USE SIGNAL ;
    PORT
      LAYER M3 ;
        RECT 782 1161.84 782.3 1162.14 ;
    END
  END D2A_BIST_ISEL[0]
  PIN D2A_BGH_CTRIM[7]
    DIRECTION INPUT ;
    USE SIGNAL ;
    PORT
      LAYER M3 ;
        RECT 725.665 835.925 725.965 836.225 ;
    END
  END D2A_BGH_CTRIM[7]
  PIN D2A_DCLEADOFF_ISEL_TRIM[1]
    DIRECTION INPUT ;
    USE SIGNAL ;
    PORT
      LAYER M3 ;
        RECT 1097.75 1646.7 1098.05 1647 ;
    END
  END D2A_DCLEADOFF_ISEL_TRIM[1]
  PIN D2A_SPARE_TRIM2[5]
    DIRECTION INPUT ;
    USE SIGNAL ;
    PORT
      LAYER M3 ;
        RECT 891.37 1367.085 891.67 1367.385 ;
    END
  END D2A_SPARE_TRIM2[5]
  PIN D2A_SDM_CLK
    DIRECTION INPUT ;
    USE SIGNAL ;
    PORT
      LAYER M3 ;
        RECT 1075.555 1646.7 1075.855 1647 ;
    END
  END D2A_SDM_CLK
  PIN D2A_SW_Z_TX_GSEL[1]
    DIRECTION INPUT ;
    USE SIGNAL ;
    PORT
      LAYER M3 ;
        RECT 1217.84 1676.605 1218.14 1676.905 ;
    END
  END D2A_SW_Z_TX_GSEL[1]
  PIN D2A_ECG_DDA_CLKSEL[0]
    DIRECTION INPUT ;
    USE SIGNAL ;
    PORT
      LAYER M3 ;
        RECT 1149.255 1646.7 1149.555 1647 ;
    END
  END D2A_ECG_DDA_CLKSEL[0]
  PIN D2A_DCLEADOFF_ISEL_TRIM[3]
    DIRECTION INPUT ;
    USE SIGNAL ;
    PORT
      LAYER M3 ;
        RECT 961.235 1464.88 961.535 1465.18 ;
    END
  END D2A_DCLEADOFF_ISEL_TRIM[3]
  PIN D2A_ACLEADOFF_ISEL_TRIM[2]
    DIRECTION INPUT ;
    USE SIGNAL ;
    PORT
      LAYER M3 ;
        RECT 948.235 1464.88 948.535 1465.18 ;
    END
  END D2A_ACLEADOFF_ISEL_TRIM[2]
  PIN D2A_TIA_GAIN[2]
    DIRECTION INPUT ;
    USE SIGNAL ;
    PORT
      LAYER M3 ;
        RECT 782 903.51 782.2 903.81 ;
    END
  END D2A_TIA_GAIN[2]
  PIN D2A_PPGDAC1_VSEL[6]
    DIRECTION INPUT ;
    USE SIGNAL ;
    PORT
      LAYER M3 ;
        RECT 782 1110.285 782.3 1110.585 ;
    END
  END D2A_PPGDAC1_VSEL[6]
  PIN D2A_SW_Z_CLK256K
    DIRECTION INPUT ;
    USE SIGNAL ;
    PORT
      LAYER M3 ;
        RECT 1217.84 1673.005 1218.14 1673.305 ;
    END
  END D2A_SW_Z_CLK256K
  PIN A2D_SPARE_TRIM_SW0[7]
    DIRECTION OUTPUT ;
    USE SIGNAL ;
    PORT
      LAYER M3 ;
        RECT 891.37 1354.39 891.67 1355.39 ;
    END
  END A2D_SPARE_TRIM_SW0[7]
  PIN D2A_SPARE_TRIM3[5]
    DIRECTION INPUT ;
    USE SIGNAL ;
    PORT
      LAYER M3 ;
        RECT 782 931.81 782.3 932.11 ;
    END
  END D2A_SPARE_TRIM3[5]
  PIN D2A_SPARE_TRIM3[3]
    DIRECTION INPUT ;
    USE SIGNAL ;
    PORT
      LAYER M3 ;
        RECT 782 929.21 782.3 929.51 ;
    END
  END D2A_SPARE_TRIM3[3]
  PIN D2A_SPARE_TRIM3[2]
    DIRECTION INPUT ;
    USE SIGNAL ;
    PORT
      LAYER M3 ;
        RECT 782 927.91 782.3 928.21 ;
    END
  END D2A_SPARE_TRIM3[2]
  OBS
    LAYER M2 ;
      POLYGON 2500 2450 1959.625 2450 1959.625 2422.09 1961.625 2422.09 1961.625 2364.34 1959.625 2364.34 1959.625 2228 1217.84 2228 1217.84 1721.215 1219.84 1721.215 1219.84 1714.155 1217.84 1714.155 1217.84 1670.505 1219.84 1670.505 1219.84 1665.005 1217.84 1665.005 1217.84 1647 1169.555 1647 1169.555 1645 1163.555 1645 1163.555 1647 1072.26 1647 1072.26 1645 1066.26 1645 1066.26 1647 1042 1647 1042 1465.18 986.735 1465.18 986.735 1463.18 981.235 1463.18 981.235 1465.18 927.235 1465.18 927.235 1463.18 921.735 1463.18 921.735 1465.18 891.37 1465.18 891.37 1387.375 893.37 1387.375 893.37 1381.875 891.37 1381.875 891.37 1360.06 893.37 1360.06 893.37 1356.26 891.37 1356.26 891.37 1332.395 893.37 1332.395 893.37 1327.895 891.37 1327.895 891.37 1236.33 782 1236.33 782 1191.54 784 1191.54 784 1186.54 782 1186.54 782 1159.215 784 1159.215 784 1154.215 782 1154.215 782 1140.83 784 1140.83 784 1136.335 782 1136.335 782 1101.02 784 1101.02 784 1095.485 782 1095.485 782 924.31 784 924.31 784 919.31 782 919.31 782 874.71 784 874.71 784 869.21 782 869.21 782 836.225 724.765 836.225 724.765 834.225 720.765 834.225 720.765 836.225 694.745 836.225 694.745 834.225 690.745 834.225 690.745 836.225 559.965 836.225 559.965 834.225 555.99 834.225 555.99 836.225 472.37 836.225 472.37 834.225 468.37 834.225 468.37 836.225 212 836.225 212 675.5 86.65 675.5 86.65 673.5 26.91 673.5 26.91 675.5 0 675.5 0 0 2500 0 ;
    LAYER M1 ;
      POLYGON 2500 2450 1959.625 2450 1959.625 2422.09 1961.625 2422.09 1961.625 2364.34 1959.625 2364.34 1959.625 2228 1217.84 2228 1217.84 1647 1042 1647 1042 1465.18 891.37 1465.18 891.37 1236.33 782 1236.33 782 836.225 212 836.225 212 675.5 86.65 675.5 86.65 673.5 26.91 673.5 26.91 675.5 0 675.5 0 0 2500 0 ;
    LAYER M5 ;
      POLYGON 2500 2450 1959.625 2450 1959.625 2422.09 1961.625 2422.09 1961.625 2364.34 1959.625 2364.34 1959.625 2228 1217.84 2228 1217.84 1721.215 1219.84 1721.215 1219.84 1665.005 1217.84 1665.005 1217.84 1647 1169.555 1647 1169.555 1645 1066.26 1645 1066.26 1647 1042 1647 1042 1465.18 986.735 1465.18 986.735 1463.18 921.735 1463.18 921.735 1465.18 891.37 1465.18 891.37 1387.375 893.37 1387.375 893.37 1327.895 891.37 1327.895 891.37 1236.33 782 1236.33 782 1203.9 784 1203.9 784 1095.485 782 1095.485 782 936.71 784 936.71 784 869.21 782 869.21 782 836.225 267.5 836.225 267.5 834.225 218 834.225 218 836.225 212 836.225 212 825.31 214 825.31 214 810.24 212 810.24 212 675.5 86.65 675.5 86.65 673.5 26.91 673.5 26.91 675.5 0 675.5 0 0 2500 0 ;
    LAYER M3 ;
      POLYGON 2500 2450 1959.625 2450 1959.625 2422.09 1961.625 2422.09 1961.625 2364.34 1959.625 2364.34 1959.625 2228 1217.84 2228 1217.84 1721.215 1219.84 1721.215 1219.84 1665.005 1217.84 1665.005 1217.84 1647 1169.555 1647 1169.555 1645 1066.26 1645 1066.26 1647 1042 1647 1042 1465.18 986.735 1465.18 986.735 1463.18 921.735 1463.18 921.735 1465.18 891.37 1465.18 891.37 1387.375 893.37 1387.375 893.37 1327.895 891.37 1327.895 891.37 1236.33 782 1236.33 782 1203.9 784 1203.9 784 1095.485 782 1095.485 782 936.71 784 936.71 784 869.21 782 869.21 782 836.225 737.365 836.225 737.365 834.225 267.5 834.225 267.5 836.225 212 836.225 212 825.31 214 825.31 214 810.24 212 810.24 212 675.5 86.65 675.5 86.65 673.5 26.91 673.5 26.91 675.5 0 675.5 0 0 2500 0 ;
    LAYER M4 ;
      POLYGON 2500 2450 1959.625 2450 1959.625 2422.09 1961.625 2422.09 1961.625 2364.34 1959.625 2364.34 1959.625 2228 1217.84 2228 1217.84 1721.215 1219.84 1721.215 1219.84 1665.005 1217.84 1665.005 1217.84 1647 1169.555 1647 1169.555 1645 1066.26 1645 1066.26 1647 1042 1647 1042 1465.18 986.735 1465.18 986.735 1463.18 921.735 1463.18 921.735 1465.18 891.37 1465.18 891.37 1387.375 893.37 1387.375 893.37 1327.895 891.37 1327.895 891.37 1236.33 782 1236.33 782 1203.9 784 1203.9 784 1095.485 782 1095.485 782 936.71 784 936.71 784 869.21 782 869.21 782 836.225 737.365 836.225 737.365 834.225 267.5 834.225 267.5 836.225 212 836.225 212 825.31 214 825.31 214 810.24 212 810.24 212 675.5 86.65 675.5 86.65 673.5 26.91 673.5 26.91 675.5 0 675.5 0 0 2500 0 ;
    LAYER OVERLAP ;
      POLYGON  2500 2450  1959.625 2450  1959.625 2228  1217.84 2228  1217.84 1647  1042 1647  1042 1465.18  891.37 1465.18  891.37 1236.33  782 1236.33  782 836.225  212 836.225  212 675.5  0 675.5  0 0  2500 0 ;
  END
  PROPERTY lastSavedExtractCounter 73136 ;
  PROPERTY CatenaDesignType "chipAssembly" ;
END BAF4P1_ANA_CHIP

END LIBRARY
